# OpenTallas memory compiler (tools/mem_compiler), ASAP7 abstract view
VERSION 5.7 ;
BUSBITCHARS "[]" ;
DIVIDERCHAR "/" ;
PROPERTYDEFINITIONS
  MACRO width INTEGER ;
  MACRO depth INTEGER ;
  MACRO banks INTEGER ;
END PROPERTYDEFINITIONS
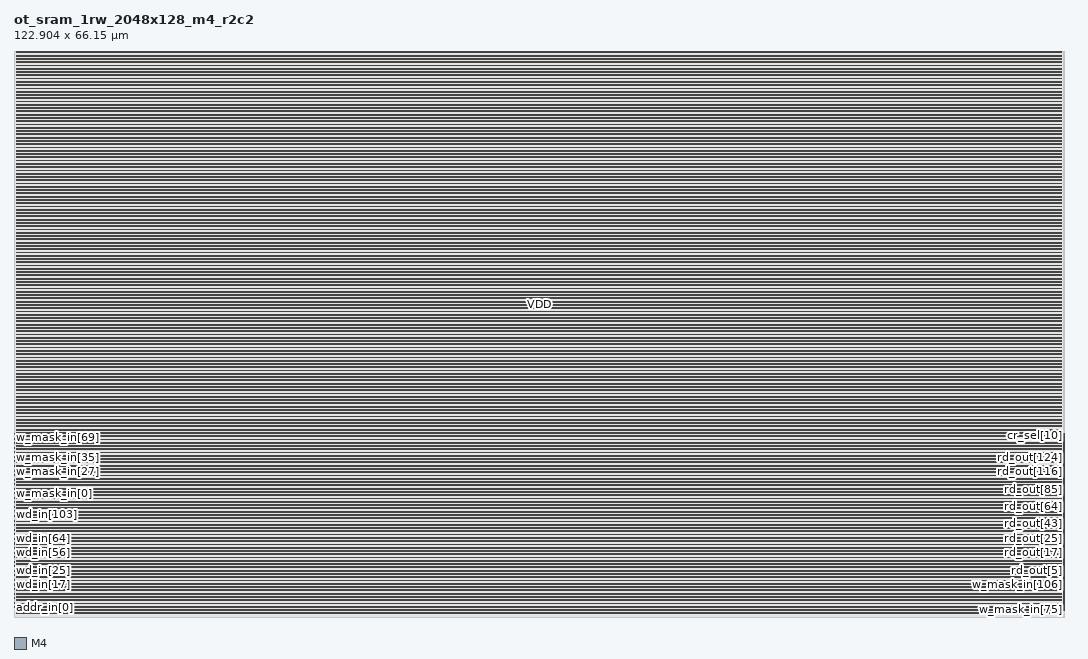
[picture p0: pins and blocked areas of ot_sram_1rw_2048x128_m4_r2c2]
MACRO ot_sram_1rw_2048x128_m4_r2c2
  PROPERTY width 128 ;
  PROPERTY depth 2048 ;
  PROPERTY banks 1 ;
  FOREIGN ot_sram_1rw_2048x128_m4_r2c2 0 0 ;
  SYMMETRY X Y R90 ;
  SIZE 122.904 BY 66.150 ;
  CLASS BLOCK ;
  PIN clk
    DIRECTION INPUT ;
    USE CLOCK ;
    SHAPE ABUTMENT ;
    PORT
      LAYER M4 ;
      RECT 0.000 0.768 0.024 0.792 ;
    END
  END clk
  PIN ce_in
    DIRECTION INPUT ;
    USE SIGNAL ;
    SHAPE ABUTMENT ;
    PORT
      LAYER M4 ;
      RECT 0.000 0.864 0.024 0.888 ;
    END
  END ce_in
  PIN we_in
    DIRECTION INPUT ;
    USE SIGNAL ;
    SHAPE ABUTMENT ;
    PORT
      LAYER M4 ;
      RECT 0.000 0.960 0.024 0.984 ;
    END
  END we_in
  PIN addr_in[0]
    DIRECTION INPUT ;
    USE SIGNAL ;
    SHAPE ABUTMENT ;
    PORT
      LAYER M4 ;
      RECT 0.000 1.056 0.024 1.080 ;
    END
  END addr_in[0]
  PIN addr_in[1]
    DIRECTION INPUT ;
    USE SIGNAL ;
    SHAPE ABUTMENT ;
    PORT
      LAYER M4 ;
      RECT 0.000 1.152 0.024 1.176 ;
    END
  END addr_in[1]
  PIN addr_in[2]
    DIRECTION INPUT ;
    USE SIGNAL ;
    SHAPE ABUTMENT ;
    PORT
      LAYER M4 ;
      RECT 0.000 1.248 0.024 1.272 ;
    END
  END addr_in[2]
  PIN addr_in[3]
    DIRECTION INPUT ;
    USE SIGNAL ;
    SHAPE ABUTMENT ;
    PORT
      LAYER M4 ;
      RECT 0.000 1.344 0.024 1.368 ;
    END
  END addr_in[3]
  PIN addr_in[4]
    DIRECTION INPUT ;
    USE SIGNAL ;
    SHAPE ABUTMENT ;
    PORT
      LAYER M4 ;
      RECT 0.000 1.440 0.024 1.464 ;
    END
  END addr_in[4]
  PIN addr_in[5]
    DIRECTION INPUT ;
    USE SIGNAL ;
    SHAPE ABUTMENT ;
    PORT
      LAYER M4 ;
      RECT 0.000 1.536 0.024 1.560 ;
    END
  END addr_in[5]
  PIN addr_in[6]
    DIRECTION INPUT ;
    USE SIGNAL ;
    SHAPE ABUTMENT ;
    PORT
      LAYER M4 ;
      RECT 0.000 1.632 0.024 1.656 ;
    END
  END addr_in[6]
  PIN addr_in[7]
    DIRECTION INPUT ;
    USE SIGNAL ;
    SHAPE ABUTMENT ;
    PORT
      LAYER M4 ;
      RECT 0.000 1.728 0.024 1.752 ;
    END
  END addr_in[7]
  PIN addr_in[8]
    DIRECTION INPUT ;
    USE SIGNAL ;
    SHAPE ABUTMENT ;
    PORT
      LAYER M4 ;
      RECT 0.000 1.824 0.024 1.848 ;
    END
  END addr_in[8]
  PIN addr_in[9]
    DIRECTION INPUT ;
    USE SIGNAL ;
    SHAPE ABUTMENT ;
    PORT
      LAYER M4 ;
      RECT 0.000 1.920 0.024 1.944 ;
    END
  END addr_in[9]
  PIN addr_in[10]
    DIRECTION INPUT ;
    USE SIGNAL ;
    SHAPE ABUTMENT ;
    PORT
      LAYER M4 ;
      RECT 0.000 2.016 0.024 2.040 ;
    END
  END addr_in[10]
  PIN wd_in[0]
    DIRECTION INPUT ;
    USE SIGNAL ;
    SHAPE ABUTMENT ;
    PORT
      LAYER M4 ;
      RECT 0.000 2.112 0.024 2.136 ;
    END
  END wd_in[0]
  PIN wd_in[1]
    DIRECTION INPUT ;
    USE SIGNAL ;
    SHAPE ABUTMENT ;
    PORT
      LAYER M4 ;
      RECT 0.000 2.208 0.024 2.232 ;
    END
  END wd_in[1]
  PIN wd_in[2]
    DIRECTION INPUT ;
    USE SIGNAL ;
    SHAPE ABUTMENT ;
    PORT
      LAYER M4 ;
      RECT 0.000 2.304 0.024 2.328 ;
    END
  END wd_in[2]
  PIN wd_in[3]
    DIRECTION INPUT ;
    USE SIGNAL ;
    SHAPE ABUTMENT ;
    PORT
      LAYER M4 ;
      RECT 0.000 2.400 0.024 2.424 ;
    END
  END wd_in[3]
  PIN wd_in[4]
    DIRECTION INPUT ;
    USE SIGNAL ;
    SHAPE ABUTMENT ;
    PORT
      LAYER M4 ;
      RECT 0.000 2.496 0.024 2.520 ;
    END
  END wd_in[4]
  PIN wd_in[5]
    DIRECTION INPUT ;
    USE SIGNAL ;
    SHAPE ABUTMENT ;
    PORT
      LAYER M4 ;
      RECT 0.000 2.592 0.024 2.616 ;
    END
  END wd_in[5]
  PIN wd_in[6]
    DIRECTION INPUT ;
    USE SIGNAL ;
    SHAPE ABUTMENT ;
    PORT
      LAYER M4 ;
      RECT 0.000 2.688 0.024 2.712 ;
    END
  END wd_in[6]
  PIN wd_in[7]
    DIRECTION INPUT ;
    USE SIGNAL ;
    SHAPE ABUTMENT ;
    PORT
      LAYER M4 ;
      RECT 0.000 2.784 0.024 2.808 ;
    END
  END wd_in[7]
  PIN wd_in[8]
    DIRECTION INPUT ;
    USE SIGNAL ;
    SHAPE ABUTMENT ;
    PORT
      LAYER M4 ;
      RECT 0.000 2.880 0.024 2.904 ;
    END
  END wd_in[8]
  PIN wd_in[9]
    DIRECTION INPUT ;
    USE SIGNAL ;
    SHAPE ABUTMENT ;
    PORT
      LAYER M4 ;
      RECT 0.000 2.976 0.024 3.000 ;
    END
  END wd_in[9]
  PIN wd_in[10]
    DIRECTION INPUT ;
    USE SIGNAL ;
    SHAPE ABUTMENT ;
    PORT
      LAYER M4 ;
      RECT 0.000 3.072 0.024 3.096 ;
    END
  END wd_in[10]
  PIN wd_in[11]
    DIRECTION INPUT ;
    USE SIGNAL ;
    SHAPE ABUTMENT ;
    PORT
      LAYER M4 ;
      RECT 0.000 3.168 0.024 3.192 ;
    END
  END wd_in[11]
  PIN wd_in[12]
    DIRECTION INPUT ;
    USE SIGNAL ;
    SHAPE ABUTMENT ;
    PORT
      LAYER M4 ;
      RECT 0.000 3.264 0.024 3.288 ;
    END
  END wd_in[12]
  PIN wd_in[13]
    DIRECTION INPUT ;
    USE SIGNAL ;
    SHAPE ABUTMENT ;
    PORT
      LAYER M4 ;
      RECT 0.000 3.360 0.024 3.384 ;
    END
  END wd_in[13]
  PIN wd_in[14]
    DIRECTION INPUT ;
    USE SIGNAL ;
    SHAPE ABUTMENT ;
    PORT
      LAYER M4 ;
      RECT 0.000 3.456 0.024 3.480 ;
    END
  END wd_in[14]
  PIN wd_in[15]
    DIRECTION INPUT ;
    USE SIGNAL ;
    SHAPE ABUTMENT ;
    PORT
      LAYER M4 ;
      RECT 0.000 3.552 0.024 3.576 ;
    END
  END wd_in[15]
  PIN wd_in[16]
    DIRECTION INPUT ;
    USE SIGNAL ;
    SHAPE ABUTMENT ;
    PORT
      LAYER M4 ;
      RECT 0.000 3.648 0.024 3.672 ;
    END
  END wd_in[16]
  PIN wd_in[17]
    DIRECTION INPUT ;
    USE SIGNAL ;
    SHAPE ABUTMENT ;
    PORT
      LAYER M4 ;
      RECT 0.000 3.744 0.024 3.768 ;
    END
  END wd_in[17]
  PIN wd_in[18]
    DIRECTION INPUT ;
    USE SIGNAL ;
    SHAPE ABUTMENT ;
    PORT
      LAYER M4 ;
      RECT 0.000 3.840 0.024 3.864 ;
    END
  END wd_in[18]
  PIN wd_in[19]
    DIRECTION INPUT ;
    USE SIGNAL ;
    SHAPE ABUTMENT ;
    PORT
      LAYER M4 ;
      RECT 0.000 3.936 0.024 3.960 ;
    END
  END wd_in[19]
  PIN wd_in[20]
    DIRECTION INPUT ;
    USE SIGNAL ;
    SHAPE ABUTMENT ;
    PORT
      LAYER M4 ;
      RECT 0.000 4.032 0.024 4.056 ;
    END
  END wd_in[20]
  PIN wd_in[21]
    DIRECTION INPUT ;
    USE SIGNAL ;
    SHAPE ABUTMENT ;
    PORT
      LAYER M4 ;
      RECT 0.000 4.128 0.024 4.152 ;
    END
  END wd_in[21]
  PIN wd_in[22]
    DIRECTION INPUT ;
    USE SIGNAL ;
    SHAPE ABUTMENT ;
    PORT
      LAYER M4 ;
      RECT 0.000 4.224 0.024 4.248 ;
    END
  END wd_in[22]
  PIN wd_in[23]
    DIRECTION INPUT ;
    USE SIGNAL ;
    SHAPE ABUTMENT ;
    PORT
      LAYER M4 ;
      RECT 0.000 4.320 0.024 4.344 ;
    END
  END wd_in[23]
  PIN wd_in[24]
    DIRECTION INPUT ;
    USE SIGNAL ;
    SHAPE ABUTMENT ;
    PORT
      LAYER M4 ;
      RECT 0.000 4.416 0.024 4.440 ;
    END
  END wd_in[24]
  PIN wd_in[25]
    DIRECTION INPUT ;
    USE SIGNAL ;
    SHAPE ABUTMENT ;
    PORT
      LAYER M4 ;
      RECT 0.000 4.512 0.024 4.536 ;
    END
  END wd_in[25]
  PIN wd_in[26]
    DIRECTION INPUT ;
    USE SIGNAL ;
    SHAPE ABUTMENT ;
    PORT
      LAYER M4 ;
      RECT 0.000 4.608 0.024 4.632 ;
    END
  END wd_in[26]
  PIN wd_in[27]
    DIRECTION INPUT ;
    USE SIGNAL ;
    SHAPE ABUTMENT ;
    PORT
      LAYER M4 ;
      RECT 0.000 4.704 0.024 4.728 ;
    END
  END wd_in[27]
  PIN wd_in[28]
    DIRECTION INPUT ;
    USE SIGNAL ;
    SHAPE ABUTMENT ;
    PORT
      LAYER M4 ;
      RECT 0.000 4.800 0.024 4.824 ;
    END
  END wd_in[28]
  PIN wd_in[29]
    DIRECTION INPUT ;
    USE SIGNAL ;
    SHAPE ABUTMENT ;
    PORT
      LAYER M4 ;
      RECT 0.000 4.896 0.024 4.920 ;
    END
  END wd_in[29]
  PIN wd_in[30]
    DIRECTION INPUT ;
    USE SIGNAL ;
    SHAPE ABUTMENT ;
    PORT
      LAYER M4 ;
      RECT 0.000 4.992 0.024 5.016 ;
    END
  END wd_in[30]
  PIN wd_in[31]
    DIRECTION INPUT ;
    USE SIGNAL ;
    SHAPE ABUTMENT ;
    PORT
      LAYER M4 ;
      RECT 0.000 5.088 0.024 5.112 ;
    END
  END wd_in[31]
  PIN wd_in[32]
    DIRECTION INPUT ;
    USE SIGNAL ;
    SHAPE ABUTMENT ;
    PORT
      LAYER M4 ;
      RECT 0.000 5.184 0.024 5.208 ;
    END
  END wd_in[32]
  PIN wd_in[33]
    DIRECTION INPUT ;
    USE SIGNAL ;
    SHAPE ABUTMENT ;
    PORT
      LAYER M4 ;
      RECT 0.000 5.280 0.024 5.304 ;
    END
  END wd_in[33]
  PIN wd_in[34]
    DIRECTION INPUT ;
    USE SIGNAL ;
    SHAPE ABUTMENT ;
    PORT
      LAYER M4 ;
      RECT 0.000 5.376 0.024 5.400 ;
    END
  END wd_in[34]
  PIN wd_in[35]
    DIRECTION INPUT ;
    USE SIGNAL ;
    SHAPE ABUTMENT ;
    PORT
      LAYER M4 ;
      RECT 0.000 5.472 0.024 5.496 ;
    END
  END wd_in[35]
  PIN wd_in[36]
    DIRECTION INPUT ;
    USE SIGNAL ;
    SHAPE ABUTMENT ;
    PORT
      LAYER M4 ;
      RECT 0.000 5.568 0.024 5.592 ;
    END
  END wd_in[36]
  PIN wd_in[37]
    DIRECTION INPUT ;
    USE SIGNAL ;
    SHAPE ABUTMENT ;
    PORT
      LAYER M4 ;
      RECT 0.000 5.664 0.024 5.688 ;
    END
  END wd_in[37]
  PIN wd_in[38]
    DIRECTION INPUT ;
    USE SIGNAL ;
    SHAPE ABUTMENT ;
    PORT
      LAYER M4 ;
      RECT 0.000 5.760 0.024 5.784 ;
    END
  END wd_in[38]
  PIN wd_in[39]
    DIRECTION INPUT ;
    USE SIGNAL ;
    SHAPE ABUTMENT ;
    PORT
      LAYER M4 ;
      RECT 0.000 5.856 0.024 5.880 ;
    END
  END wd_in[39]
  PIN wd_in[40]
    DIRECTION INPUT ;
    USE SIGNAL ;
    SHAPE ABUTMENT ;
    PORT
      LAYER M4 ;
      RECT 0.000 5.952 0.024 5.976 ;
    END
  END wd_in[40]
  PIN wd_in[41]
    DIRECTION INPUT ;
    USE SIGNAL ;
    SHAPE ABUTMENT ;
    PORT
      LAYER M4 ;
      RECT 0.000 6.048 0.024 6.072 ;
    END
  END wd_in[41]
  PIN wd_in[42]
    DIRECTION INPUT ;
    USE SIGNAL ;
    SHAPE ABUTMENT ;
    PORT
      LAYER M4 ;
      RECT 0.000 6.144 0.024 6.168 ;
    END
  END wd_in[42]
  PIN wd_in[43]
    DIRECTION INPUT ;
    USE SIGNAL ;
    SHAPE ABUTMENT ;
    PORT
      LAYER M4 ;
      RECT 0.000 6.240 0.024 6.264 ;
    END
  END wd_in[43]
  PIN wd_in[44]
    DIRECTION INPUT ;
    USE SIGNAL ;
    SHAPE ABUTMENT ;
    PORT
      LAYER M4 ;
      RECT 0.000 6.336 0.024 6.360 ;
    END
  END wd_in[44]
  PIN wd_in[45]
    DIRECTION INPUT ;
    USE SIGNAL ;
    SHAPE ABUTMENT ;
    PORT
      LAYER M4 ;
      RECT 0.000 6.432 0.024 6.456 ;
    END
  END wd_in[45]
  PIN wd_in[46]
    DIRECTION INPUT ;
    USE SIGNAL ;
    SHAPE ABUTMENT ;
    PORT
      LAYER M4 ;
      RECT 0.000 6.528 0.024 6.552 ;
    END
  END wd_in[46]
  PIN wd_in[47]
    DIRECTION INPUT ;
    USE SIGNAL ;
    SHAPE ABUTMENT ;
    PORT
      LAYER M4 ;
      RECT 0.000 6.624 0.024 6.648 ;
    END
  END wd_in[47]
  PIN wd_in[48]
    DIRECTION INPUT ;
    USE SIGNAL ;
    SHAPE ABUTMENT ;
    PORT
      LAYER M4 ;
      RECT 0.000 6.720 0.024 6.744 ;
    END
  END wd_in[48]
  PIN wd_in[49]
    DIRECTION INPUT ;
    USE SIGNAL ;
    SHAPE ABUTMENT ;
    PORT
      LAYER M4 ;
      RECT 0.000 6.816 0.024 6.840 ;
    END
  END wd_in[49]
  PIN wd_in[50]
    DIRECTION INPUT ;
    USE SIGNAL ;
    SHAPE ABUTMENT ;
    PORT
      LAYER M4 ;
      RECT 0.000 6.912 0.024 6.936 ;
    END
  END wd_in[50]
  PIN wd_in[51]
    DIRECTION INPUT ;
    USE SIGNAL ;
    SHAPE ABUTMENT ;
    PORT
      LAYER M4 ;
      RECT 0.000 7.008 0.024 7.032 ;
    END
  END wd_in[51]
  PIN wd_in[52]
    DIRECTION INPUT ;
    USE SIGNAL ;
    SHAPE ABUTMENT ;
    PORT
      LAYER M4 ;
      RECT 0.000 7.104 0.024 7.128 ;
    END
  END wd_in[52]
  PIN wd_in[53]
    DIRECTION INPUT ;
    USE SIGNAL ;
    SHAPE ABUTMENT ;
    PORT
      LAYER M4 ;
      RECT 0.000 7.200 0.024 7.224 ;
    END
  END wd_in[53]
  PIN wd_in[54]
    DIRECTION INPUT ;
    USE SIGNAL ;
    SHAPE ABUTMENT ;
    PORT
      LAYER M4 ;
      RECT 0.000 7.296 0.024 7.320 ;
    END
  END wd_in[54]
  PIN wd_in[55]
    DIRECTION INPUT ;
    USE SIGNAL ;
    SHAPE ABUTMENT ;
    PORT
      LAYER M4 ;
      RECT 0.000 7.392 0.024 7.416 ;
    END
  END wd_in[55]
  PIN wd_in[56]
    DIRECTION INPUT ;
    USE SIGNAL ;
    SHAPE ABUTMENT ;
    PORT
      LAYER M4 ;
      RECT 0.000 7.488 0.024 7.512 ;
    END
  END wd_in[56]
  PIN wd_in[57]
    DIRECTION INPUT ;
    USE SIGNAL ;
    SHAPE ABUTMENT ;
    PORT
      LAYER M4 ;
      RECT 0.000 7.584 0.024 7.608 ;
    END
  END wd_in[57]
  PIN wd_in[58]
    DIRECTION INPUT ;
    USE SIGNAL ;
    SHAPE ABUTMENT ;
    PORT
      LAYER M4 ;
      RECT 0.000 7.680 0.024 7.704 ;
    END
  END wd_in[58]
  PIN wd_in[59]
    DIRECTION INPUT ;
    USE SIGNAL ;
    SHAPE ABUTMENT ;
    PORT
      LAYER M4 ;
      RECT 0.000 7.776 0.024 7.800 ;
    END
  END wd_in[59]
  PIN wd_in[60]
    DIRECTION INPUT ;
    USE SIGNAL ;
    SHAPE ABUTMENT ;
    PORT
      LAYER M4 ;
      RECT 0.000 7.872 0.024 7.896 ;
    END
  END wd_in[60]
  PIN wd_in[61]
    DIRECTION INPUT ;
    USE SIGNAL ;
    SHAPE ABUTMENT ;
    PORT
      LAYER M4 ;
      RECT 0.000 7.968 0.024 7.992 ;
    END
  END wd_in[61]
  PIN wd_in[62]
    DIRECTION INPUT ;
    USE SIGNAL ;
    SHAPE ABUTMENT ;
    PORT
      LAYER M4 ;
      RECT 0.000 8.064 0.024 8.088 ;
    END
  END wd_in[62]
  PIN wd_in[63]
    DIRECTION INPUT ;
    USE SIGNAL ;
    SHAPE ABUTMENT ;
    PORT
      LAYER M4 ;
      RECT 0.000 8.160 0.024 8.184 ;
    END
  END wd_in[63]
  PIN wd_in[64]
    DIRECTION INPUT ;
    USE SIGNAL ;
    SHAPE ABUTMENT ;
    PORT
      LAYER M4 ;
      RECT 0.000 8.256 0.024 8.280 ;
    END
  END wd_in[64]
  PIN wd_in[65]
    DIRECTION INPUT ;
    USE SIGNAL ;
    SHAPE ABUTMENT ;
    PORT
      LAYER M4 ;
      RECT 0.000 8.352 0.024 8.376 ;
    END
  END wd_in[65]
  PIN wd_in[66]
    DIRECTION INPUT ;
    USE SIGNAL ;
    SHAPE ABUTMENT ;
    PORT
      LAYER M4 ;
      RECT 0.000 8.448 0.024 8.472 ;
    END
  END wd_in[66]
  PIN wd_in[67]
    DIRECTION INPUT ;
    USE SIGNAL ;
    SHAPE ABUTMENT ;
    PORT
      LAYER M4 ;
      RECT 0.000 8.544 0.024 8.568 ;
    END
  END wd_in[67]
  PIN wd_in[68]
    DIRECTION INPUT ;
    USE SIGNAL ;
    SHAPE ABUTMENT ;
    PORT
      LAYER M4 ;
      RECT 0.000 8.640 0.024 8.664 ;
    END
  END wd_in[68]
  PIN wd_in[69]
    DIRECTION INPUT ;
    USE SIGNAL ;
    SHAPE ABUTMENT ;
    PORT
      LAYER M4 ;
      RECT 0.000 8.736 0.024 8.760 ;
    END
  END wd_in[69]
  PIN wd_in[70]
    DIRECTION INPUT ;
    USE SIGNAL ;
    SHAPE ABUTMENT ;
    PORT
      LAYER M4 ;
      RECT 0.000 8.832 0.024 8.856 ;
    END
  END wd_in[70]
  PIN wd_in[71]
    DIRECTION INPUT ;
    USE SIGNAL ;
    SHAPE ABUTMENT ;
    PORT
      LAYER M4 ;
      RECT 0.000 8.928 0.024 8.952 ;
    END
  END wd_in[71]
  PIN wd_in[72]
    DIRECTION INPUT ;
    USE SIGNAL ;
    SHAPE ABUTMENT ;
    PORT
      LAYER M4 ;
      RECT 0.000 9.024 0.024 9.048 ;
    END
  END wd_in[72]
  PIN wd_in[73]
    DIRECTION INPUT ;
    USE SIGNAL ;
    SHAPE ABUTMENT ;
    PORT
      LAYER M4 ;
      RECT 0.000 9.120 0.024 9.144 ;
    END
  END wd_in[73]
  PIN wd_in[74]
    DIRECTION INPUT ;
    USE SIGNAL ;
    SHAPE ABUTMENT ;
    PORT
      LAYER M4 ;
      RECT 0.000 9.216 0.024 9.240 ;
    END
  END wd_in[74]
  PIN wd_in[75]
    DIRECTION INPUT ;
    USE SIGNAL ;
    SHAPE ABUTMENT ;
    PORT
      LAYER M4 ;
      RECT 0.000 9.312 0.024 9.336 ;
    END
  END wd_in[75]
  PIN wd_in[76]
    DIRECTION INPUT ;
    USE SIGNAL ;
    SHAPE ABUTMENT ;
    PORT
      LAYER M4 ;
      RECT 0.000 9.408 0.024 9.432 ;
    END
  END wd_in[76]
  PIN wd_in[77]
    DIRECTION INPUT ;
    USE SIGNAL ;
    SHAPE ABUTMENT ;
    PORT
      LAYER M4 ;
      RECT 0.000 9.504 0.024 9.528 ;
    END
  END wd_in[77]
  PIN wd_in[78]
    DIRECTION INPUT ;
    USE SIGNAL ;
    SHAPE ABUTMENT ;
    PORT
      LAYER M4 ;
      RECT 0.000 9.600 0.024 9.624 ;
    END
  END wd_in[78]
  PIN wd_in[79]
    DIRECTION INPUT ;
    USE SIGNAL ;
    SHAPE ABUTMENT ;
    PORT
      LAYER M4 ;
      RECT 0.000 9.696 0.024 9.720 ;
    END
  END wd_in[79]
  PIN wd_in[80]
    DIRECTION INPUT ;
    USE SIGNAL ;
    SHAPE ABUTMENT ;
    PORT
      LAYER M4 ;
      RECT 0.000 9.792 0.024 9.816 ;
    END
  END wd_in[80]
  PIN wd_in[81]
    DIRECTION INPUT ;
    USE SIGNAL ;
    SHAPE ABUTMENT ;
    PORT
      LAYER M4 ;
      RECT 0.000 9.888 0.024 9.912 ;
    END
  END wd_in[81]
  PIN wd_in[82]
    DIRECTION INPUT ;
    USE SIGNAL ;
    SHAPE ABUTMENT ;
    PORT
      LAYER M4 ;
      RECT 0.000 9.984 0.024 10.008 ;
    END
  END wd_in[82]
  PIN wd_in[83]
    DIRECTION INPUT ;
    USE SIGNAL ;
    SHAPE ABUTMENT ;
    PORT
      LAYER M4 ;
      RECT 0.000 10.080 0.024 10.104 ;
    END
  END wd_in[83]
  PIN wd_in[84]
    DIRECTION INPUT ;
    USE SIGNAL ;
    SHAPE ABUTMENT ;
    PORT
      LAYER M4 ;
      RECT 0.000 10.176 0.024 10.200 ;
    END
  END wd_in[84]
  PIN wd_in[85]
    DIRECTION INPUT ;
    USE SIGNAL ;
    SHAPE ABUTMENT ;
    PORT
      LAYER M4 ;
      RECT 0.000 10.272 0.024 10.296 ;
    END
  END wd_in[85]
  PIN wd_in[86]
    DIRECTION INPUT ;
    USE SIGNAL ;
    SHAPE ABUTMENT ;
    PORT
      LAYER M4 ;
      RECT 0.000 10.368 0.024 10.392 ;
    END
  END wd_in[86]
  PIN wd_in[87]
    DIRECTION INPUT ;
    USE SIGNAL ;
    SHAPE ABUTMENT ;
    PORT
      LAYER M4 ;
      RECT 0.000 10.464 0.024 10.488 ;
    END
  END wd_in[87]
  PIN wd_in[88]
    DIRECTION INPUT ;
    USE SIGNAL ;
    SHAPE ABUTMENT ;
    PORT
      LAYER M4 ;
      RECT 0.000 10.560 0.024 10.584 ;
    END
  END wd_in[88]
  PIN wd_in[89]
    DIRECTION INPUT ;
    USE SIGNAL ;
    SHAPE ABUTMENT ;
    PORT
      LAYER M4 ;
      RECT 0.000 10.656 0.024 10.680 ;
    END
  END wd_in[89]
  PIN wd_in[90]
    DIRECTION INPUT ;
    USE SIGNAL ;
    SHAPE ABUTMENT ;
    PORT
      LAYER M4 ;
      RECT 0.000 10.752 0.024 10.776 ;
    END
  END wd_in[90]
  PIN wd_in[91]
    DIRECTION INPUT ;
    USE SIGNAL ;
    SHAPE ABUTMENT ;
    PORT
      LAYER M4 ;
      RECT 0.000 10.848 0.024 10.872 ;
    END
  END wd_in[91]
  PIN wd_in[92]
    DIRECTION INPUT ;
    USE SIGNAL ;
    SHAPE ABUTMENT ;
    PORT
      LAYER M4 ;
      RECT 0.000 10.944 0.024 10.968 ;
    END
  END wd_in[92]
  PIN wd_in[93]
    DIRECTION INPUT ;
    USE SIGNAL ;
    SHAPE ABUTMENT ;
    PORT
      LAYER M4 ;
      RECT 0.000 11.040 0.024 11.064 ;
    END
  END wd_in[93]
  PIN wd_in[94]
    DIRECTION INPUT ;
    USE SIGNAL ;
    SHAPE ABUTMENT ;
    PORT
      LAYER M4 ;
      RECT 0.000 11.136 0.024 11.160 ;
    END
  END wd_in[94]
  PIN wd_in[95]
    DIRECTION INPUT ;
    USE SIGNAL ;
    SHAPE ABUTMENT ;
    PORT
      LAYER M4 ;
      RECT 0.000 11.232 0.024 11.256 ;
    END
  END wd_in[95]
  PIN wd_in[96]
    DIRECTION INPUT ;
    USE SIGNAL ;
    SHAPE ABUTMENT ;
    PORT
      LAYER M4 ;
      RECT 0.000 11.328 0.024 11.352 ;
    END
  END wd_in[96]
  PIN wd_in[97]
    DIRECTION INPUT ;
    USE SIGNAL ;
    SHAPE ABUTMENT ;
    PORT
      LAYER M4 ;
      RECT 0.000 11.424 0.024 11.448 ;
    END
  END wd_in[97]
  PIN wd_in[98]
    DIRECTION INPUT ;
    USE SIGNAL ;
    SHAPE ABUTMENT ;
    PORT
      LAYER M4 ;
      RECT 0.000 11.520 0.024 11.544 ;
    END
  END wd_in[98]
  PIN wd_in[99]
    DIRECTION INPUT ;
    USE SIGNAL ;
    SHAPE ABUTMENT ;
    PORT
      LAYER M4 ;
      RECT 0.000 11.616 0.024 11.640 ;
    END
  END wd_in[99]
  PIN wd_in[100]
    DIRECTION INPUT ;
    USE SIGNAL ;
    SHAPE ABUTMENT ;
    PORT
      LAYER M4 ;
      RECT 0.000 11.712 0.024 11.736 ;
    END
  END wd_in[100]
  PIN wd_in[101]
    DIRECTION INPUT ;
    USE SIGNAL ;
    SHAPE ABUTMENT ;
    PORT
      LAYER M4 ;
      RECT 0.000 11.808 0.024 11.832 ;
    END
  END wd_in[101]
  PIN wd_in[102]
    DIRECTION INPUT ;
    USE SIGNAL ;
    SHAPE ABUTMENT ;
    PORT
      LAYER M4 ;
      RECT 0.000 11.904 0.024 11.928 ;
    END
  END wd_in[102]
  PIN wd_in[103]
    DIRECTION INPUT ;
    USE SIGNAL ;
    SHAPE ABUTMENT ;
    PORT
      LAYER M4 ;
      RECT 0.000 12.000 0.024 12.024 ;
    END
  END wd_in[103]
  PIN wd_in[104]
    DIRECTION INPUT ;
    USE SIGNAL ;
    SHAPE ABUTMENT ;
    PORT
      LAYER M4 ;
      RECT 0.000 12.096 0.024 12.120 ;
    END
  END wd_in[104]
  PIN wd_in[105]
    DIRECTION INPUT ;
    USE SIGNAL ;
    SHAPE ABUTMENT ;
    PORT
      LAYER M4 ;
      RECT 0.000 12.192 0.024 12.216 ;
    END
  END wd_in[105]
  PIN wd_in[106]
    DIRECTION INPUT ;
    USE SIGNAL ;
    SHAPE ABUTMENT ;
    PORT
      LAYER M4 ;
      RECT 0.000 12.288 0.024 12.312 ;
    END
  END wd_in[106]
  PIN wd_in[107]
    DIRECTION INPUT ;
    USE SIGNAL ;
    SHAPE ABUTMENT ;
    PORT
      LAYER M4 ;
      RECT 0.000 12.384 0.024 12.408 ;
    END
  END wd_in[107]
  PIN wd_in[108]
    DIRECTION INPUT ;
    USE SIGNAL ;
    SHAPE ABUTMENT ;
    PORT
      LAYER M4 ;
      RECT 0.000 12.480 0.024 12.504 ;
    END
  END wd_in[108]
  PIN wd_in[109]
    DIRECTION INPUT ;
    USE SIGNAL ;
    SHAPE ABUTMENT ;
    PORT
      LAYER M4 ;
      RECT 0.000 12.576 0.024 12.600 ;
    END
  END wd_in[109]
  PIN wd_in[110]
    DIRECTION INPUT ;
    USE SIGNAL ;
    SHAPE ABUTMENT ;
    PORT
      LAYER M4 ;
      RECT 0.000 12.672 0.024 12.696 ;
    END
  END wd_in[110]
  PIN wd_in[111]
    DIRECTION INPUT ;
    USE SIGNAL ;
    SHAPE ABUTMENT ;
    PORT
      LAYER M4 ;
      RECT 0.000 12.768 0.024 12.792 ;
    END
  END wd_in[111]
  PIN wd_in[112]
    DIRECTION INPUT ;
    USE SIGNAL ;
    SHAPE ABUTMENT ;
    PORT
      LAYER M4 ;
      RECT 0.000 12.864 0.024 12.888 ;
    END
  END wd_in[112]
  PIN wd_in[113]
    DIRECTION INPUT ;
    USE SIGNAL ;
    SHAPE ABUTMENT ;
    PORT
      LAYER M4 ;
      RECT 0.000 12.960 0.024 12.984 ;
    END
  END wd_in[113]
  PIN wd_in[114]
    DIRECTION INPUT ;
    USE SIGNAL ;
    SHAPE ABUTMENT ;
    PORT
      LAYER M4 ;
      RECT 0.000 13.056 0.024 13.080 ;
    END
  END wd_in[114]
  PIN wd_in[115]
    DIRECTION INPUT ;
    USE SIGNAL ;
    SHAPE ABUTMENT ;
    PORT
      LAYER M4 ;
      RECT 0.000 13.152 0.024 13.176 ;
    END
  END wd_in[115]
  PIN wd_in[116]
    DIRECTION INPUT ;
    USE SIGNAL ;
    SHAPE ABUTMENT ;
    PORT
      LAYER M4 ;
      RECT 0.000 13.248 0.024 13.272 ;
    END
  END wd_in[116]
  PIN wd_in[117]
    DIRECTION INPUT ;
    USE SIGNAL ;
    SHAPE ABUTMENT ;
    PORT
      LAYER M4 ;
      RECT 0.000 13.344 0.024 13.368 ;
    END
  END wd_in[117]
  PIN wd_in[118]
    DIRECTION INPUT ;
    USE SIGNAL ;
    SHAPE ABUTMENT ;
    PORT
      LAYER M4 ;
      RECT 0.000 13.440 0.024 13.464 ;
    END
  END wd_in[118]
  PIN wd_in[119]
    DIRECTION INPUT ;
    USE SIGNAL ;
    SHAPE ABUTMENT ;
    PORT
      LAYER M4 ;
      RECT 0.000 13.536 0.024 13.560 ;
    END
  END wd_in[119]
  PIN wd_in[120]
    DIRECTION INPUT ;
    USE SIGNAL ;
    SHAPE ABUTMENT ;
    PORT
      LAYER M4 ;
      RECT 0.000 13.632 0.024 13.656 ;
    END
  END wd_in[120]
  PIN wd_in[121]
    DIRECTION INPUT ;
    USE SIGNAL ;
    SHAPE ABUTMENT ;
    PORT
      LAYER M4 ;
      RECT 0.000 13.728 0.024 13.752 ;
    END
  END wd_in[121]
  PIN wd_in[122]
    DIRECTION INPUT ;
    USE SIGNAL ;
    SHAPE ABUTMENT ;
    PORT
      LAYER M4 ;
      RECT 0.000 13.824 0.024 13.848 ;
    END
  END wd_in[122]
  PIN wd_in[123]
    DIRECTION INPUT ;
    USE SIGNAL ;
    SHAPE ABUTMENT ;
    PORT
      LAYER M4 ;
      RECT 0.000 13.920 0.024 13.944 ;
    END
  END wd_in[123]
  PIN wd_in[124]
    DIRECTION INPUT ;
    USE SIGNAL ;
    SHAPE ABUTMENT ;
    PORT
      LAYER M4 ;
      RECT 0.000 14.016 0.024 14.040 ;
    END
  END wd_in[124]
  PIN wd_in[125]
    DIRECTION INPUT ;
    USE SIGNAL ;
    SHAPE ABUTMENT ;
    PORT
      LAYER M4 ;
      RECT 0.000 14.112 0.024 14.136 ;
    END
  END wd_in[125]
  PIN wd_in[126]
    DIRECTION INPUT ;
    USE SIGNAL ;
    SHAPE ABUTMENT ;
    PORT
      LAYER M4 ;
      RECT 0.000 14.208 0.024 14.232 ;
    END
  END wd_in[126]
  PIN wd_in[127]
    DIRECTION INPUT ;
    USE SIGNAL ;
    SHAPE ABUTMENT ;
    PORT
      LAYER M4 ;
      RECT 0.000 14.304 0.024 14.328 ;
    END
  END wd_in[127]
  PIN w_mask_in[0]
    DIRECTION INPUT ;
    USE SIGNAL ;
    SHAPE ABUTMENT ;
    PORT
      LAYER M4 ;
      RECT 0.000 14.400 0.024 14.424 ;
    END
  END w_mask_in[0]
  PIN w_mask_in[1]
    DIRECTION INPUT ;
    USE SIGNAL ;
    SHAPE ABUTMENT ;
    PORT
      LAYER M4 ;
      RECT 0.000 14.496 0.024 14.520 ;
    END
  END w_mask_in[1]
  PIN w_mask_in[2]
    DIRECTION INPUT ;
    USE SIGNAL ;
    SHAPE ABUTMENT ;
    PORT
      LAYER M4 ;
      RECT 0.000 14.592 0.024 14.616 ;
    END
  END w_mask_in[2]
  PIN w_mask_in[3]
    DIRECTION INPUT ;
    USE SIGNAL ;
    SHAPE ABUTMENT ;
    PORT
      LAYER M4 ;
      RECT 0.000 14.688 0.024 14.712 ;
    END
  END w_mask_in[3]
  PIN w_mask_in[4]
    DIRECTION INPUT ;
    USE SIGNAL ;
    SHAPE ABUTMENT ;
    PORT
      LAYER M4 ;
      RECT 0.000 14.784 0.024 14.808 ;
    END
  END w_mask_in[4]
  PIN w_mask_in[5]
    DIRECTION INPUT ;
    USE SIGNAL ;
    SHAPE ABUTMENT ;
    PORT
      LAYER M4 ;
      RECT 0.000 14.880 0.024 14.904 ;
    END
  END w_mask_in[5]
  PIN w_mask_in[6]
    DIRECTION INPUT ;
    USE SIGNAL ;
    SHAPE ABUTMENT ;
    PORT
      LAYER M4 ;
      RECT 0.000 14.976 0.024 15.000 ;
    END
  END w_mask_in[6]
  PIN w_mask_in[7]
    DIRECTION INPUT ;
    USE SIGNAL ;
    SHAPE ABUTMENT ;
    PORT
      LAYER M4 ;
      RECT 0.000 15.072 0.024 15.096 ;
    END
  END w_mask_in[7]
  PIN w_mask_in[8]
    DIRECTION INPUT ;
    USE SIGNAL ;
    SHAPE ABUTMENT ;
    PORT
      LAYER M4 ;
      RECT 0.000 15.168 0.024 15.192 ;
    END
  END w_mask_in[8]
  PIN w_mask_in[9]
    DIRECTION INPUT ;
    USE SIGNAL ;
    SHAPE ABUTMENT ;
    PORT
      LAYER M4 ;
      RECT 0.000 15.264 0.024 15.288 ;
    END
  END w_mask_in[9]
  PIN w_mask_in[10]
    DIRECTION INPUT ;
    USE SIGNAL ;
    SHAPE ABUTMENT ;
    PORT
      LAYER M4 ;
      RECT 0.000 15.360 0.024 15.384 ;
    END
  END w_mask_in[10]
  PIN w_mask_in[11]
    DIRECTION INPUT ;
    USE SIGNAL ;
    SHAPE ABUTMENT ;
    PORT
      LAYER M4 ;
      RECT 0.000 15.456 0.024 15.480 ;
    END
  END w_mask_in[11]
  PIN w_mask_in[12]
    DIRECTION INPUT ;
    USE SIGNAL ;
    SHAPE ABUTMENT ;
    PORT
      LAYER M4 ;
      RECT 0.000 15.552 0.024 15.576 ;
    END
  END w_mask_in[12]
  PIN w_mask_in[13]
    DIRECTION INPUT ;
    USE SIGNAL ;
    SHAPE ABUTMENT ;
    PORT
      LAYER M4 ;
      RECT 0.000 15.648 0.024 15.672 ;
    END
  END w_mask_in[13]
  PIN w_mask_in[14]
    DIRECTION INPUT ;
    USE SIGNAL ;
    SHAPE ABUTMENT ;
    PORT
      LAYER M4 ;
      RECT 0.000 15.744 0.024 15.768 ;
    END
  END w_mask_in[14]
  PIN w_mask_in[15]
    DIRECTION INPUT ;
    USE SIGNAL ;
    SHAPE ABUTMENT ;
    PORT
      LAYER M4 ;
      RECT 0.000 15.840 0.024 15.864 ;
    END
  END w_mask_in[15]
  PIN w_mask_in[16]
    DIRECTION INPUT ;
    USE SIGNAL ;
    SHAPE ABUTMENT ;
    PORT
      LAYER M4 ;
      RECT 0.000 15.936 0.024 15.960 ;
    END
  END w_mask_in[16]
  PIN w_mask_in[17]
    DIRECTION INPUT ;
    USE SIGNAL ;
    SHAPE ABUTMENT ;
    PORT
      LAYER M4 ;
      RECT 0.000 16.032 0.024 16.056 ;
    END
  END w_mask_in[17]
  PIN w_mask_in[18]
    DIRECTION INPUT ;
    USE SIGNAL ;
    SHAPE ABUTMENT ;
    PORT
      LAYER M4 ;
      RECT 0.000 16.128 0.024 16.152 ;
    END
  END w_mask_in[18]
  PIN w_mask_in[19]
    DIRECTION INPUT ;
    USE SIGNAL ;
    SHAPE ABUTMENT ;
    PORT
      LAYER M4 ;
      RECT 0.000 16.224 0.024 16.248 ;
    END
  END w_mask_in[19]
  PIN w_mask_in[20]
    DIRECTION INPUT ;
    USE SIGNAL ;
    SHAPE ABUTMENT ;
    PORT
      LAYER M4 ;
      RECT 0.000 16.320 0.024 16.344 ;
    END
  END w_mask_in[20]
  PIN w_mask_in[21]
    DIRECTION INPUT ;
    USE SIGNAL ;
    SHAPE ABUTMENT ;
    PORT
      LAYER M4 ;
      RECT 0.000 16.416 0.024 16.440 ;
    END
  END w_mask_in[21]
  PIN w_mask_in[22]
    DIRECTION INPUT ;
    USE SIGNAL ;
    SHAPE ABUTMENT ;
    PORT
      LAYER M4 ;
      RECT 0.000 16.512 0.024 16.536 ;
    END
  END w_mask_in[22]
  PIN w_mask_in[23]
    DIRECTION INPUT ;
    USE SIGNAL ;
    SHAPE ABUTMENT ;
    PORT
      LAYER M4 ;
      RECT 0.000 16.608 0.024 16.632 ;
    END
  END w_mask_in[23]
  PIN w_mask_in[24]
    DIRECTION INPUT ;
    USE SIGNAL ;
    SHAPE ABUTMENT ;
    PORT
      LAYER M4 ;
      RECT 0.000 16.704 0.024 16.728 ;
    END
  END w_mask_in[24]
  PIN w_mask_in[25]
    DIRECTION INPUT ;
    USE SIGNAL ;
    SHAPE ABUTMENT ;
    PORT
      LAYER M4 ;
      RECT 0.000 16.800 0.024 16.824 ;
    END
  END w_mask_in[25]
  PIN w_mask_in[26]
    DIRECTION INPUT ;
    USE SIGNAL ;
    SHAPE ABUTMENT ;
    PORT
      LAYER M4 ;
      RECT 0.000 16.896 0.024 16.920 ;
    END
  END w_mask_in[26]
  PIN w_mask_in[27]
    DIRECTION INPUT ;
    USE SIGNAL ;
    SHAPE ABUTMENT ;
    PORT
      LAYER M4 ;
      RECT 0.000 16.992 0.024 17.016 ;
    END
  END w_mask_in[27]
  PIN w_mask_in[28]
    DIRECTION INPUT ;
    USE SIGNAL ;
    SHAPE ABUTMENT ;
    PORT
      LAYER M4 ;
      RECT 0.000 17.088 0.024 17.112 ;
    END
  END w_mask_in[28]
  PIN w_mask_in[29]
    DIRECTION INPUT ;
    USE SIGNAL ;
    SHAPE ABUTMENT ;
    PORT
      LAYER M4 ;
      RECT 0.000 17.184 0.024 17.208 ;
    END
  END w_mask_in[29]
  PIN w_mask_in[30]
    DIRECTION INPUT ;
    USE SIGNAL ;
    SHAPE ABUTMENT ;
    PORT
      LAYER M4 ;
      RECT 0.000 17.280 0.024 17.304 ;
    END
  END w_mask_in[30]
  PIN w_mask_in[31]
    DIRECTION INPUT ;
    USE SIGNAL ;
    SHAPE ABUTMENT ;
    PORT
      LAYER M4 ;
      RECT 0.000 17.376 0.024 17.400 ;
    END
  END w_mask_in[31]
  PIN w_mask_in[32]
    DIRECTION INPUT ;
    USE SIGNAL ;
    SHAPE ABUTMENT ;
    PORT
      LAYER M4 ;
      RECT 0.000 17.472 0.024 17.496 ;
    END
  END w_mask_in[32]
  PIN w_mask_in[33]
    DIRECTION INPUT ;
    USE SIGNAL ;
    SHAPE ABUTMENT ;
    PORT
      LAYER M4 ;
      RECT 0.000 17.568 0.024 17.592 ;
    END
  END w_mask_in[33]
  PIN w_mask_in[34]
    DIRECTION INPUT ;
    USE SIGNAL ;
    SHAPE ABUTMENT ;
    PORT
      LAYER M4 ;
      RECT 0.000 17.664 0.024 17.688 ;
    END
  END w_mask_in[34]
  PIN w_mask_in[35]
    DIRECTION INPUT ;
    USE SIGNAL ;
    SHAPE ABUTMENT ;
    PORT
      LAYER M4 ;
      RECT 0.000 17.760 0.024 17.784 ;
    END
  END w_mask_in[35]
  PIN w_mask_in[36]
    DIRECTION INPUT ;
    USE SIGNAL ;
    SHAPE ABUTMENT ;
    PORT
      LAYER M4 ;
      RECT 0.000 17.856 0.024 17.880 ;
    END
  END w_mask_in[36]
  PIN w_mask_in[37]
    DIRECTION INPUT ;
    USE SIGNAL ;
    SHAPE ABUTMENT ;
    PORT
      LAYER M4 ;
      RECT 0.000 17.952 0.024 17.976 ;
    END
  END w_mask_in[37]
  PIN w_mask_in[38]
    DIRECTION INPUT ;
    USE SIGNAL ;
    SHAPE ABUTMENT ;
    PORT
      LAYER M4 ;
      RECT 0.000 18.048 0.024 18.072 ;
    END
  END w_mask_in[38]
  PIN w_mask_in[39]
    DIRECTION INPUT ;
    USE SIGNAL ;
    SHAPE ABUTMENT ;
    PORT
      LAYER M4 ;
      RECT 0.000 18.144 0.024 18.168 ;
    END
  END w_mask_in[39]
  PIN w_mask_in[40]
    DIRECTION INPUT ;
    USE SIGNAL ;
    SHAPE ABUTMENT ;
    PORT
      LAYER M4 ;
      RECT 0.000 18.240 0.024 18.264 ;
    END
  END w_mask_in[40]
  PIN w_mask_in[41]
    DIRECTION INPUT ;
    USE SIGNAL ;
    SHAPE ABUTMENT ;
    PORT
      LAYER M4 ;
      RECT 0.000 18.336 0.024 18.360 ;
    END
  END w_mask_in[41]
  PIN w_mask_in[42]
    DIRECTION INPUT ;
    USE SIGNAL ;
    SHAPE ABUTMENT ;
    PORT
      LAYER M4 ;
      RECT 0.000 18.432 0.024 18.456 ;
    END
  END w_mask_in[42]
  PIN w_mask_in[43]
    DIRECTION INPUT ;
    USE SIGNAL ;
    SHAPE ABUTMENT ;
    PORT
      LAYER M4 ;
      RECT 0.000 18.528 0.024 18.552 ;
    END
  END w_mask_in[43]
  PIN w_mask_in[44]
    DIRECTION INPUT ;
    USE SIGNAL ;
    SHAPE ABUTMENT ;
    PORT
      LAYER M4 ;
      RECT 0.000 18.624 0.024 18.648 ;
    END
  END w_mask_in[44]
  PIN w_mask_in[45]
    DIRECTION INPUT ;
    USE SIGNAL ;
    SHAPE ABUTMENT ;
    PORT
      LAYER M4 ;
      RECT 0.000 18.720 0.024 18.744 ;
    END
  END w_mask_in[45]
  PIN w_mask_in[46]
    DIRECTION INPUT ;
    USE SIGNAL ;
    SHAPE ABUTMENT ;
    PORT
      LAYER M4 ;
      RECT 0.000 18.816 0.024 18.840 ;
    END
  END w_mask_in[46]
  PIN w_mask_in[47]
    DIRECTION INPUT ;
    USE SIGNAL ;
    SHAPE ABUTMENT ;
    PORT
      LAYER M4 ;
      RECT 0.000 18.912 0.024 18.936 ;
    END
  END w_mask_in[47]
  PIN w_mask_in[48]
    DIRECTION INPUT ;
    USE SIGNAL ;
    SHAPE ABUTMENT ;
    PORT
      LAYER M4 ;
      RECT 0.000 19.008 0.024 19.032 ;
    END
  END w_mask_in[48]
  PIN w_mask_in[49]
    DIRECTION INPUT ;
    USE SIGNAL ;
    SHAPE ABUTMENT ;
    PORT
      LAYER M4 ;
      RECT 0.000 19.104 0.024 19.128 ;
    END
  END w_mask_in[49]
  PIN w_mask_in[50]
    DIRECTION INPUT ;
    USE SIGNAL ;
    SHAPE ABUTMENT ;
    PORT
      LAYER M4 ;
      RECT 0.000 19.200 0.024 19.224 ;
    END
  END w_mask_in[50]
  PIN w_mask_in[51]
    DIRECTION INPUT ;
    USE SIGNAL ;
    SHAPE ABUTMENT ;
    PORT
      LAYER M4 ;
      RECT 0.000 19.296 0.024 19.320 ;
    END
  END w_mask_in[51]
  PIN w_mask_in[52]
    DIRECTION INPUT ;
    USE SIGNAL ;
    SHAPE ABUTMENT ;
    PORT
      LAYER M4 ;
      RECT 0.000 19.392 0.024 19.416 ;
    END
  END w_mask_in[52]
  PIN w_mask_in[53]
    DIRECTION INPUT ;
    USE SIGNAL ;
    SHAPE ABUTMENT ;
    PORT
      LAYER M4 ;
      RECT 0.000 19.488 0.024 19.512 ;
    END
  END w_mask_in[53]
  PIN w_mask_in[54]
    DIRECTION INPUT ;
    USE SIGNAL ;
    SHAPE ABUTMENT ;
    PORT
      LAYER M4 ;
      RECT 0.000 19.584 0.024 19.608 ;
    END
  END w_mask_in[54]
  PIN w_mask_in[55]
    DIRECTION INPUT ;
    USE SIGNAL ;
    SHAPE ABUTMENT ;
    PORT
      LAYER M4 ;
      RECT 0.000 19.680 0.024 19.704 ;
    END
  END w_mask_in[55]
  PIN w_mask_in[56]
    DIRECTION INPUT ;
    USE SIGNAL ;
    SHAPE ABUTMENT ;
    PORT
      LAYER M4 ;
      RECT 0.000 19.776 0.024 19.800 ;
    END
  END w_mask_in[56]
  PIN w_mask_in[57]
    DIRECTION INPUT ;
    USE SIGNAL ;
    SHAPE ABUTMENT ;
    PORT
      LAYER M4 ;
      RECT 0.000 19.872 0.024 19.896 ;
    END
  END w_mask_in[57]
  PIN w_mask_in[58]
    DIRECTION INPUT ;
    USE SIGNAL ;
    SHAPE ABUTMENT ;
    PORT
      LAYER M4 ;
      RECT 0.000 19.968 0.024 19.992 ;
    END
  END w_mask_in[58]
  PIN w_mask_in[59]
    DIRECTION INPUT ;
    USE SIGNAL ;
    SHAPE ABUTMENT ;
    PORT
      LAYER M4 ;
      RECT 0.000 20.064 0.024 20.088 ;
    END
  END w_mask_in[59]
  PIN w_mask_in[60]
    DIRECTION INPUT ;
    USE SIGNAL ;
    SHAPE ABUTMENT ;
    PORT
      LAYER M4 ;
      RECT 0.000 20.160 0.024 20.184 ;
    END
  END w_mask_in[60]
  PIN w_mask_in[61]
    DIRECTION INPUT ;
    USE SIGNAL ;
    SHAPE ABUTMENT ;
    PORT
      LAYER M4 ;
      RECT 0.000 20.256 0.024 20.280 ;
    END
  END w_mask_in[61]
  PIN w_mask_in[62]
    DIRECTION INPUT ;
    USE SIGNAL ;
    SHAPE ABUTMENT ;
    PORT
      LAYER M4 ;
      RECT 0.000 20.352 0.024 20.376 ;
    END
  END w_mask_in[62]
  PIN w_mask_in[63]
    DIRECTION INPUT ;
    USE SIGNAL ;
    SHAPE ABUTMENT ;
    PORT
      LAYER M4 ;
      RECT 0.000 20.448 0.024 20.472 ;
    END
  END w_mask_in[63]
  PIN w_mask_in[64]
    DIRECTION INPUT ;
    USE SIGNAL ;
    SHAPE ABUTMENT ;
    PORT
      LAYER M4 ;
      RECT 0.000 20.544 0.024 20.568 ;
    END
  END w_mask_in[64]
  PIN w_mask_in[65]
    DIRECTION INPUT ;
    USE SIGNAL ;
    SHAPE ABUTMENT ;
    PORT
      LAYER M4 ;
      RECT 0.000 20.640 0.024 20.664 ;
    END
  END w_mask_in[65]
  PIN w_mask_in[66]
    DIRECTION INPUT ;
    USE SIGNAL ;
    SHAPE ABUTMENT ;
    PORT
      LAYER M4 ;
      RECT 0.000 20.736 0.024 20.760 ;
    END
  END w_mask_in[66]
  PIN w_mask_in[67]
    DIRECTION INPUT ;
    USE SIGNAL ;
    SHAPE ABUTMENT ;
    PORT
      LAYER M4 ;
      RECT 0.000 20.832 0.024 20.856 ;
    END
  END w_mask_in[67]
  PIN w_mask_in[68]
    DIRECTION INPUT ;
    USE SIGNAL ;
    SHAPE ABUTMENT ;
    PORT
      LAYER M4 ;
      RECT 0.000 20.928 0.024 20.952 ;
    END
  END w_mask_in[68]
  PIN w_mask_in[69]
    DIRECTION INPUT ;
    USE SIGNAL ;
    SHAPE ABUTMENT ;
    PORT
      LAYER M4 ;
      RECT 0.000 21.024 0.024 21.048 ;
    END
  END w_mask_in[69]
  PIN w_mask_in[70]
    DIRECTION INPUT ;
    USE SIGNAL ;
    SHAPE ABUTMENT ;
    PORT
      LAYER M4 ;
      RECT 0.000 21.120 0.024 21.144 ;
    END
  END w_mask_in[70]
  PIN w_mask_in[71]
    DIRECTION INPUT ;
    USE SIGNAL ;
    SHAPE ABUTMENT ;
    PORT
      LAYER M4 ;
      RECT 0.000 21.216 0.024 21.240 ;
    END
  END w_mask_in[71]
  PIN w_mask_in[72]
    DIRECTION INPUT ;
    USE SIGNAL ;
    SHAPE ABUTMENT ;
    PORT
      LAYER M4 ;
      RECT 0.000 21.312 0.024 21.336 ;
    END
  END w_mask_in[72]
  PIN w_mask_in[73]
    DIRECTION INPUT ;
    USE SIGNAL ;
    SHAPE ABUTMENT ;
    PORT
      LAYER M4 ;
      RECT 0.000 21.408 0.024 21.432 ;
    END
  END w_mask_in[73]
  PIN w_mask_in[74]
    DIRECTION INPUT ;
    USE SIGNAL ;
    SHAPE ABUTMENT ;
    PORT
      LAYER M4 ;
      RECT 0.000 21.504 0.024 21.528 ;
    END
  END w_mask_in[74]
  PIN w_mask_in[75]
    DIRECTION INPUT ;
    USE SIGNAL ;
    SHAPE ABUTMENT ;
    PORT
      LAYER M4 ;
      RECT 122.880 0.768 122.904 0.792 ;
    END
  END w_mask_in[75]
  PIN w_mask_in[76]
    DIRECTION INPUT ;
    USE SIGNAL ;
    SHAPE ABUTMENT ;
    PORT
      LAYER M4 ;
      RECT 122.880 0.864 122.904 0.888 ;
    END
  END w_mask_in[76]
  PIN w_mask_in[77]
    DIRECTION INPUT ;
    USE SIGNAL ;
    SHAPE ABUTMENT ;
    PORT
      LAYER M4 ;
      RECT 122.880 0.960 122.904 0.984 ;
    END
  END w_mask_in[77]
  PIN w_mask_in[78]
    DIRECTION INPUT ;
    USE SIGNAL ;
    SHAPE ABUTMENT ;
    PORT
      LAYER M4 ;
      RECT 122.880 1.056 122.904 1.080 ;
    END
  END w_mask_in[78]
  PIN w_mask_in[79]
    DIRECTION INPUT ;
    USE SIGNAL ;
    SHAPE ABUTMENT ;
    PORT
      LAYER M4 ;
      RECT 122.880 1.152 122.904 1.176 ;
    END
  END w_mask_in[79]
  PIN w_mask_in[80]
    DIRECTION INPUT ;
    USE SIGNAL ;
    SHAPE ABUTMENT ;
    PORT
      LAYER M4 ;
      RECT 122.880 1.248 122.904 1.272 ;
    END
  END w_mask_in[80]
  PIN w_mask_in[81]
    DIRECTION INPUT ;
    USE SIGNAL ;
    SHAPE ABUTMENT ;
    PORT
      LAYER M4 ;
      RECT 122.880 1.344 122.904 1.368 ;
    END
  END w_mask_in[81]
  PIN w_mask_in[82]
    DIRECTION INPUT ;
    USE SIGNAL ;
    SHAPE ABUTMENT ;
    PORT
      LAYER M4 ;
      RECT 122.880 1.440 122.904 1.464 ;
    END
  END w_mask_in[82]
  PIN w_mask_in[83]
    DIRECTION INPUT ;
    USE SIGNAL ;
    SHAPE ABUTMENT ;
    PORT
      LAYER M4 ;
      RECT 122.880 1.536 122.904 1.560 ;
    END
  END w_mask_in[83]
  PIN w_mask_in[84]
    DIRECTION INPUT ;
    USE SIGNAL ;
    SHAPE ABUTMENT ;
    PORT
      LAYER M4 ;
      RECT 122.880 1.632 122.904 1.656 ;
    END
  END w_mask_in[84]
  PIN w_mask_in[85]
    DIRECTION INPUT ;
    USE SIGNAL ;
    SHAPE ABUTMENT ;
    PORT
      LAYER M4 ;
      RECT 122.880 1.728 122.904 1.752 ;
    END
  END w_mask_in[85]
  PIN w_mask_in[86]
    DIRECTION INPUT ;
    USE SIGNAL ;
    SHAPE ABUTMENT ;
    PORT
      LAYER M4 ;
      RECT 122.880 1.824 122.904 1.848 ;
    END
  END w_mask_in[86]
  PIN w_mask_in[87]
    DIRECTION INPUT ;
    USE SIGNAL ;
    SHAPE ABUTMENT ;
    PORT
      LAYER M4 ;
      RECT 122.880 1.920 122.904 1.944 ;
    END
  END w_mask_in[87]
  PIN w_mask_in[88]
    DIRECTION INPUT ;
    USE SIGNAL ;
    SHAPE ABUTMENT ;
    PORT
      LAYER M4 ;
      RECT 122.880 2.016 122.904 2.040 ;
    END
  END w_mask_in[88]
  PIN w_mask_in[89]
    DIRECTION INPUT ;
    USE SIGNAL ;
    SHAPE ABUTMENT ;
    PORT
      LAYER M4 ;
      RECT 122.880 2.112 122.904 2.136 ;
    END
  END w_mask_in[89]
  PIN w_mask_in[90]
    DIRECTION INPUT ;
    USE SIGNAL ;
    SHAPE ABUTMENT ;
    PORT
      LAYER M4 ;
      RECT 122.880 2.208 122.904 2.232 ;
    END
  END w_mask_in[90]
  PIN w_mask_in[91]
    DIRECTION INPUT ;
    USE SIGNAL ;
    SHAPE ABUTMENT ;
    PORT
      LAYER M4 ;
      RECT 122.880 2.304 122.904 2.328 ;
    END
  END w_mask_in[91]
  PIN w_mask_in[92]
    DIRECTION INPUT ;
    USE SIGNAL ;
    SHAPE ABUTMENT ;
    PORT
      LAYER M4 ;
      RECT 122.880 2.400 122.904 2.424 ;
    END
  END w_mask_in[92]
  PIN w_mask_in[93]
    DIRECTION INPUT ;
    USE SIGNAL ;
    SHAPE ABUTMENT ;
    PORT
      LAYER M4 ;
      RECT 122.880 2.496 122.904 2.520 ;
    END
  END w_mask_in[93]
  PIN w_mask_in[94]
    DIRECTION INPUT ;
    USE SIGNAL ;
    SHAPE ABUTMENT ;
    PORT
      LAYER M4 ;
      RECT 122.880 2.592 122.904 2.616 ;
    END
  END w_mask_in[94]
  PIN w_mask_in[95]
    DIRECTION INPUT ;
    USE SIGNAL ;
    SHAPE ABUTMENT ;
    PORT
      LAYER M4 ;
      RECT 122.880 2.688 122.904 2.712 ;
    END
  END w_mask_in[95]
  PIN w_mask_in[96]
    DIRECTION INPUT ;
    USE SIGNAL ;
    SHAPE ABUTMENT ;
    PORT
      LAYER M4 ;
      RECT 122.880 2.784 122.904 2.808 ;
    END
  END w_mask_in[96]
  PIN w_mask_in[97]
    DIRECTION INPUT ;
    USE SIGNAL ;
    SHAPE ABUTMENT ;
    PORT
      LAYER M4 ;
      RECT 122.880 2.880 122.904 2.904 ;
    END
  END w_mask_in[97]
  PIN w_mask_in[98]
    DIRECTION INPUT ;
    USE SIGNAL ;
    SHAPE ABUTMENT ;
    PORT
      LAYER M4 ;
      RECT 122.880 2.976 122.904 3.000 ;
    END
  END w_mask_in[98]
  PIN w_mask_in[99]
    DIRECTION INPUT ;
    USE SIGNAL ;
    SHAPE ABUTMENT ;
    PORT
      LAYER M4 ;
      RECT 122.880 3.072 122.904 3.096 ;
    END
  END w_mask_in[99]
  PIN w_mask_in[100]
    DIRECTION INPUT ;
    USE SIGNAL ;
    SHAPE ABUTMENT ;
    PORT
      LAYER M4 ;
      RECT 122.880 3.168 122.904 3.192 ;
    END
  END w_mask_in[100]
  PIN w_mask_in[101]
    DIRECTION INPUT ;
    USE SIGNAL ;
    SHAPE ABUTMENT ;
    PORT
      LAYER M4 ;
      RECT 122.880 3.264 122.904 3.288 ;
    END
  END w_mask_in[101]
  PIN w_mask_in[102]
    DIRECTION INPUT ;
    USE SIGNAL ;
    SHAPE ABUTMENT ;
    PORT
      LAYER M4 ;
      RECT 122.880 3.360 122.904 3.384 ;
    END
  END w_mask_in[102]
  PIN w_mask_in[103]
    DIRECTION INPUT ;
    USE SIGNAL ;
    SHAPE ABUTMENT ;
    PORT
      LAYER M4 ;
      RECT 122.880 3.456 122.904 3.480 ;
    END
  END w_mask_in[103]
  PIN w_mask_in[104]
    DIRECTION INPUT ;
    USE SIGNAL ;
    SHAPE ABUTMENT ;
    PORT
      LAYER M4 ;
      RECT 122.880 3.552 122.904 3.576 ;
    END
  END w_mask_in[104]
  PIN w_mask_in[105]
    DIRECTION INPUT ;
    USE SIGNAL ;
    SHAPE ABUTMENT ;
    PORT
      LAYER M4 ;
      RECT 122.880 3.648 122.904 3.672 ;
    END
  END w_mask_in[105]
  PIN w_mask_in[106]
    DIRECTION INPUT ;
    USE SIGNAL ;
    SHAPE ABUTMENT ;
    PORT
      LAYER M4 ;
      RECT 122.880 3.744 122.904 3.768 ;
    END
  END w_mask_in[106]
  PIN w_mask_in[107]
    DIRECTION INPUT ;
    USE SIGNAL ;
    SHAPE ABUTMENT ;
    PORT
      LAYER M4 ;
      RECT 122.880 3.840 122.904 3.864 ;
    END
  END w_mask_in[107]
  PIN w_mask_in[108]
    DIRECTION INPUT ;
    USE SIGNAL ;
    SHAPE ABUTMENT ;
    PORT
      LAYER M4 ;
      RECT 122.880 3.936 122.904 3.960 ;
    END
  END w_mask_in[108]
  PIN w_mask_in[109]
    DIRECTION INPUT ;
    USE SIGNAL ;
    SHAPE ABUTMENT ;
    PORT
      LAYER M4 ;
      RECT 122.880 4.032 122.904 4.056 ;
    END
  END w_mask_in[109]
  PIN w_mask_in[110]
    DIRECTION INPUT ;
    USE SIGNAL ;
    SHAPE ABUTMENT ;
    PORT
      LAYER M4 ;
      RECT 122.880 4.128 122.904 4.152 ;
    END
  END w_mask_in[110]
  PIN w_mask_in[111]
    DIRECTION INPUT ;
    USE SIGNAL ;
    SHAPE ABUTMENT ;
    PORT
      LAYER M4 ;
      RECT 122.880 4.224 122.904 4.248 ;
    END
  END w_mask_in[111]
  PIN w_mask_in[112]
    DIRECTION INPUT ;
    USE SIGNAL ;
    SHAPE ABUTMENT ;
    PORT
      LAYER M4 ;
      RECT 122.880 4.320 122.904 4.344 ;
    END
  END w_mask_in[112]
  PIN w_mask_in[113]
    DIRECTION INPUT ;
    USE SIGNAL ;
    SHAPE ABUTMENT ;
    PORT
      LAYER M4 ;
      RECT 122.880 4.416 122.904 4.440 ;
    END
  END w_mask_in[113]
  PIN w_mask_in[114]
    DIRECTION INPUT ;
    USE SIGNAL ;
    SHAPE ABUTMENT ;
    PORT
      LAYER M4 ;
      RECT 122.880 4.512 122.904 4.536 ;
    END
  END w_mask_in[114]
  PIN w_mask_in[115]
    DIRECTION INPUT ;
    USE SIGNAL ;
    SHAPE ABUTMENT ;
    PORT
      LAYER M4 ;
      RECT 122.880 4.608 122.904 4.632 ;
    END
  END w_mask_in[115]
  PIN w_mask_in[116]
    DIRECTION INPUT ;
    USE SIGNAL ;
    SHAPE ABUTMENT ;
    PORT
      LAYER M4 ;
      RECT 122.880 4.704 122.904 4.728 ;
    END
  END w_mask_in[116]
  PIN w_mask_in[117]
    DIRECTION INPUT ;
    USE SIGNAL ;
    SHAPE ABUTMENT ;
    PORT
      LAYER M4 ;
      RECT 122.880 4.800 122.904 4.824 ;
    END
  END w_mask_in[117]
  PIN w_mask_in[118]
    DIRECTION INPUT ;
    USE SIGNAL ;
    SHAPE ABUTMENT ;
    PORT
      LAYER M4 ;
      RECT 122.880 4.896 122.904 4.920 ;
    END
  END w_mask_in[118]
  PIN w_mask_in[119]
    DIRECTION INPUT ;
    USE SIGNAL ;
    SHAPE ABUTMENT ;
    PORT
      LAYER M4 ;
      RECT 122.880 4.992 122.904 5.016 ;
    END
  END w_mask_in[119]
  PIN w_mask_in[120]
    DIRECTION INPUT ;
    USE SIGNAL ;
    SHAPE ABUTMENT ;
    PORT
      LAYER M4 ;
      RECT 122.880 5.088 122.904 5.112 ;
    END
  END w_mask_in[120]
  PIN w_mask_in[121]
    DIRECTION INPUT ;
    USE SIGNAL ;
    SHAPE ABUTMENT ;
    PORT
      LAYER M4 ;
      RECT 122.880 5.184 122.904 5.208 ;
    END
  END w_mask_in[121]
  PIN w_mask_in[122]
    DIRECTION INPUT ;
    USE SIGNAL ;
    SHAPE ABUTMENT ;
    PORT
      LAYER M4 ;
      RECT 122.880 5.280 122.904 5.304 ;
    END
  END w_mask_in[122]
  PIN w_mask_in[123]
    DIRECTION INPUT ;
    USE SIGNAL ;
    SHAPE ABUTMENT ;
    PORT
      LAYER M4 ;
      RECT 122.880 5.376 122.904 5.400 ;
    END
  END w_mask_in[123]
  PIN w_mask_in[124]
    DIRECTION INPUT ;
    USE SIGNAL ;
    SHAPE ABUTMENT ;
    PORT
      LAYER M4 ;
      RECT 122.880 5.472 122.904 5.496 ;
    END
  END w_mask_in[124]
  PIN w_mask_in[125]
    DIRECTION INPUT ;
    USE SIGNAL ;
    SHAPE ABUTMENT ;
    PORT
      LAYER M4 ;
      RECT 122.880 5.568 122.904 5.592 ;
    END
  END w_mask_in[125]
  PIN w_mask_in[126]
    DIRECTION INPUT ;
    USE SIGNAL ;
    SHAPE ABUTMENT ;
    PORT
      LAYER M4 ;
      RECT 122.880 5.664 122.904 5.688 ;
    END
  END w_mask_in[126]
  PIN w_mask_in[127]
    DIRECTION INPUT ;
    USE SIGNAL ;
    SHAPE ABUTMENT ;
    PORT
      LAYER M4 ;
      RECT 122.880 5.760 122.904 5.784 ;
    END
  END w_mask_in[127]
  PIN rd_out[0]
    DIRECTION OUTPUT ;
    USE SIGNAL ;
    SHAPE ABUTMENT ;
    PORT
      LAYER M4 ;
      RECT 122.880 5.856 122.904 5.880 ;
    END
  END rd_out[0]
  PIN rd_out[1]
    DIRECTION OUTPUT ;
    USE SIGNAL ;
    SHAPE ABUTMENT ;
    PORT
      LAYER M4 ;
      RECT 122.880 5.952 122.904 5.976 ;
    END
  END rd_out[1]
  PIN rd_out[2]
    DIRECTION OUTPUT ;
    USE SIGNAL ;
    SHAPE ABUTMENT ;
    PORT
      LAYER M4 ;
      RECT 122.880 6.048 122.904 6.072 ;
    END
  END rd_out[2]
  PIN rd_out[3]
    DIRECTION OUTPUT ;
    USE SIGNAL ;
    SHAPE ABUTMENT ;
    PORT
      LAYER M4 ;
      RECT 122.880 6.144 122.904 6.168 ;
    END
  END rd_out[3]
  PIN rd_out[4]
    DIRECTION OUTPUT ;
    USE SIGNAL ;
    SHAPE ABUTMENT ;
    PORT
      LAYER M4 ;
      RECT 122.880 6.240 122.904 6.264 ;
    END
  END rd_out[4]
  PIN rd_out[5]
    DIRECTION OUTPUT ;
    USE SIGNAL ;
    SHAPE ABUTMENT ;
    PORT
      LAYER M4 ;
      RECT 122.880 6.336 122.904 6.360 ;
    END
  END rd_out[5]
  PIN rd_out[6]
    DIRECTION OUTPUT ;
    USE SIGNAL ;
    SHAPE ABUTMENT ;
    PORT
      LAYER M4 ;
      RECT 122.880 6.432 122.904 6.456 ;
    END
  END rd_out[6]
  PIN rd_out[7]
    DIRECTION OUTPUT ;
    USE SIGNAL ;
    SHAPE ABUTMENT ;
    PORT
      LAYER M4 ;
      RECT 122.880 6.528 122.904 6.552 ;
    END
  END rd_out[7]
  PIN rd_out[8]
    DIRECTION OUTPUT ;
    USE SIGNAL ;
    SHAPE ABUTMENT ;
    PORT
      LAYER M4 ;
      RECT 122.880 6.624 122.904 6.648 ;
    END
  END rd_out[8]
  PIN rd_out[9]
    DIRECTION OUTPUT ;
    USE SIGNAL ;
    SHAPE ABUTMENT ;
    PORT
      LAYER M4 ;
      RECT 122.880 6.720 122.904 6.744 ;
    END
  END rd_out[9]
  PIN rd_out[10]
    DIRECTION OUTPUT ;
    USE SIGNAL ;
    SHAPE ABUTMENT ;
    PORT
      LAYER M4 ;
      RECT 122.880 6.816 122.904 6.840 ;
    END
  END rd_out[10]
  PIN rd_out[11]
    DIRECTION OUTPUT ;
    USE SIGNAL ;
    SHAPE ABUTMENT ;
    PORT
      LAYER M4 ;
      RECT 122.880 6.912 122.904 6.936 ;
    END
  END rd_out[11]
  PIN rd_out[12]
    DIRECTION OUTPUT ;
    USE SIGNAL ;
    SHAPE ABUTMENT ;
    PORT
      LAYER M4 ;
      RECT 122.880 7.008 122.904 7.032 ;
    END
  END rd_out[12]
  PIN rd_out[13]
    DIRECTION OUTPUT ;
    USE SIGNAL ;
    SHAPE ABUTMENT ;
    PORT
      LAYER M4 ;
      RECT 122.880 7.104 122.904 7.128 ;
    END
  END rd_out[13]
  PIN rd_out[14]
    DIRECTION OUTPUT ;
    USE SIGNAL ;
    SHAPE ABUTMENT ;
    PORT
      LAYER M4 ;
      RECT 122.880 7.200 122.904 7.224 ;
    END
  END rd_out[14]
  PIN rd_out[15]
    DIRECTION OUTPUT ;
    USE SIGNAL ;
    SHAPE ABUTMENT ;
    PORT
      LAYER M4 ;
      RECT 122.880 7.296 122.904 7.320 ;
    END
  END rd_out[15]
  PIN rd_out[16]
    DIRECTION OUTPUT ;
    USE SIGNAL ;
    SHAPE ABUTMENT ;
    PORT
      LAYER M4 ;
      RECT 122.880 7.392 122.904 7.416 ;
    END
  END rd_out[16]
  PIN rd_out[17]
    DIRECTION OUTPUT ;
    USE SIGNAL ;
    SHAPE ABUTMENT ;
    PORT
      LAYER M4 ;
      RECT 122.880 7.488 122.904 7.512 ;
    END
  END rd_out[17]
  PIN rd_out[18]
    DIRECTION OUTPUT ;
    USE SIGNAL ;
    SHAPE ABUTMENT ;
    PORT
      LAYER M4 ;
      RECT 122.880 7.584 122.904 7.608 ;
    END
  END rd_out[18]
  PIN rd_out[19]
    DIRECTION OUTPUT ;
    USE SIGNAL ;
    SHAPE ABUTMENT ;
    PORT
      LAYER M4 ;
      RECT 122.880 7.680 122.904 7.704 ;
    END
  END rd_out[19]
  PIN rd_out[20]
    DIRECTION OUTPUT ;
    USE SIGNAL ;
    SHAPE ABUTMENT ;
    PORT
      LAYER M4 ;
      RECT 122.880 7.776 122.904 7.800 ;
    END
  END rd_out[20]
  PIN rd_out[21]
    DIRECTION OUTPUT ;
    USE SIGNAL ;
    SHAPE ABUTMENT ;
    PORT
      LAYER M4 ;
      RECT 122.880 7.872 122.904 7.896 ;
    END
  END rd_out[21]
  PIN rd_out[22]
    DIRECTION OUTPUT ;
    USE SIGNAL ;
    SHAPE ABUTMENT ;
    PORT
      LAYER M4 ;
      RECT 122.880 7.968 122.904 7.992 ;
    END
  END rd_out[22]
  PIN rd_out[23]
    DIRECTION OUTPUT ;
    USE SIGNAL ;
    SHAPE ABUTMENT ;
    PORT
      LAYER M4 ;
      RECT 122.880 8.064 122.904 8.088 ;
    END
  END rd_out[23]
  PIN rd_out[24]
    DIRECTION OUTPUT ;
    USE SIGNAL ;
    SHAPE ABUTMENT ;
    PORT
      LAYER M4 ;
      RECT 122.880 8.160 122.904 8.184 ;
    END
  END rd_out[24]
  PIN rd_out[25]
    DIRECTION OUTPUT ;
    USE SIGNAL ;
    SHAPE ABUTMENT ;
    PORT
      LAYER M4 ;
      RECT 122.880 8.256 122.904 8.280 ;
    END
  END rd_out[25]
  PIN rd_out[26]
    DIRECTION OUTPUT ;
    USE SIGNAL ;
    SHAPE ABUTMENT ;
    PORT
      LAYER M4 ;
      RECT 122.880 8.352 122.904 8.376 ;
    END
  END rd_out[26]
  PIN rd_out[27]
    DIRECTION OUTPUT ;
    USE SIGNAL ;
    SHAPE ABUTMENT ;
    PORT
      LAYER M4 ;
      RECT 122.880 8.448 122.904 8.472 ;
    END
  END rd_out[27]
  PIN rd_out[28]
    DIRECTION OUTPUT ;
    USE SIGNAL ;
    SHAPE ABUTMENT ;
    PORT
      LAYER M4 ;
      RECT 122.880 8.544 122.904 8.568 ;
    END
  END rd_out[28]
  PIN rd_out[29]
    DIRECTION OUTPUT ;
    USE SIGNAL ;
    SHAPE ABUTMENT ;
    PORT
      LAYER M4 ;
      RECT 122.880 8.640 122.904 8.664 ;
    END
  END rd_out[29]
  PIN rd_out[30]
    DIRECTION OUTPUT ;
    USE SIGNAL ;
    SHAPE ABUTMENT ;
    PORT
      LAYER M4 ;
      RECT 122.880 8.736 122.904 8.760 ;
    END
  END rd_out[30]
  PIN rd_out[31]
    DIRECTION OUTPUT ;
    USE SIGNAL ;
    SHAPE ABUTMENT ;
    PORT
      LAYER M4 ;
      RECT 122.880 8.832 122.904 8.856 ;
    END
  END rd_out[31]
  PIN rd_out[32]
    DIRECTION OUTPUT ;
    USE SIGNAL ;
    SHAPE ABUTMENT ;
    PORT
      LAYER M4 ;
      RECT 122.880 8.928 122.904 8.952 ;
    END
  END rd_out[32]
  PIN rd_out[33]
    DIRECTION OUTPUT ;
    USE SIGNAL ;
    SHAPE ABUTMENT ;
    PORT
      LAYER M4 ;
      RECT 122.880 9.024 122.904 9.048 ;
    END
  END rd_out[33]
  PIN rd_out[34]
    DIRECTION OUTPUT ;
    USE SIGNAL ;
    SHAPE ABUTMENT ;
    PORT
      LAYER M4 ;
      RECT 122.880 9.120 122.904 9.144 ;
    END
  END rd_out[34]
  PIN rd_out[35]
    DIRECTION OUTPUT ;
    USE SIGNAL ;
    SHAPE ABUTMENT ;
    PORT
      LAYER M4 ;
      RECT 122.880 9.216 122.904 9.240 ;
    END
  END rd_out[35]
  PIN rd_out[36]
    DIRECTION OUTPUT ;
    USE SIGNAL ;
    SHAPE ABUTMENT ;
    PORT
      LAYER M4 ;
      RECT 122.880 9.312 122.904 9.336 ;
    END
  END rd_out[36]
  PIN rd_out[37]
    DIRECTION OUTPUT ;
    USE SIGNAL ;
    SHAPE ABUTMENT ;
    PORT
      LAYER M4 ;
      RECT 122.880 9.408 122.904 9.432 ;
    END
  END rd_out[37]
  PIN rd_out[38]
    DIRECTION OUTPUT ;
    USE SIGNAL ;
    SHAPE ABUTMENT ;
    PORT
      LAYER M4 ;
      RECT 122.880 9.504 122.904 9.528 ;
    END
  END rd_out[38]
  PIN rd_out[39]
    DIRECTION OUTPUT ;
    USE SIGNAL ;
    SHAPE ABUTMENT ;
    PORT
      LAYER M4 ;
      RECT 122.880 9.600 122.904 9.624 ;
    END
  END rd_out[39]
  PIN rd_out[40]
    DIRECTION OUTPUT ;
    USE SIGNAL ;
    SHAPE ABUTMENT ;
    PORT
      LAYER M4 ;
      RECT 122.880 9.696 122.904 9.720 ;
    END
  END rd_out[40]
  PIN rd_out[41]
    DIRECTION OUTPUT ;
    USE SIGNAL ;
    SHAPE ABUTMENT ;
    PORT
      LAYER M4 ;
      RECT 122.880 9.792 122.904 9.816 ;
    END
  END rd_out[41]
  PIN rd_out[42]
    DIRECTION OUTPUT ;
    USE SIGNAL ;
    SHAPE ABUTMENT ;
    PORT
      LAYER M4 ;
      RECT 122.880 9.888 122.904 9.912 ;
    END
  END rd_out[42]
  PIN rd_out[43]
    DIRECTION OUTPUT ;
    USE SIGNAL ;
    SHAPE ABUTMENT ;
    PORT
      LAYER M4 ;
      RECT 122.880 9.984 122.904 10.008 ;
    END
  END rd_out[43]
  PIN rd_out[44]
    DIRECTION OUTPUT ;
    USE SIGNAL ;
    SHAPE ABUTMENT ;
    PORT
      LAYER M4 ;
      RECT 122.880 10.080 122.904 10.104 ;
    END
  END rd_out[44]
  PIN rd_out[45]
    DIRECTION OUTPUT ;
    USE SIGNAL ;
    SHAPE ABUTMENT ;
    PORT
      LAYER M4 ;
      RECT 122.880 10.176 122.904 10.200 ;
    END
  END rd_out[45]
  PIN rd_out[46]
    DIRECTION OUTPUT ;
    USE SIGNAL ;
    SHAPE ABUTMENT ;
    PORT
      LAYER M4 ;
      RECT 122.880 10.272 122.904 10.296 ;
    END
  END rd_out[46]
  PIN rd_out[47]
    DIRECTION OUTPUT ;
    USE SIGNAL ;
    SHAPE ABUTMENT ;
    PORT
      LAYER M4 ;
      RECT 122.880 10.368 122.904 10.392 ;
    END
  END rd_out[47]
  PIN rd_out[48]
    DIRECTION OUTPUT ;
    USE SIGNAL ;
    SHAPE ABUTMENT ;
    PORT
      LAYER M4 ;
      RECT 122.880 10.464 122.904 10.488 ;
    END
  END rd_out[48]
  PIN rd_out[49]
    DIRECTION OUTPUT ;
    USE SIGNAL ;
    SHAPE ABUTMENT ;
    PORT
      LAYER M4 ;
      RECT 122.880 10.560 122.904 10.584 ;
    END
  END rd_out[49]
  PIN rd_out[50]
    DIRECTION OUTPUT ;
    USE SIGNAL ;
    SHAPE ABUTMENT ;
    PORT
      LAYER M4 ;
      RECT 122.880 10.656 122.904 10.680 ;
    END
  END rd_out[50]
  PIN rd_out[51]
    DIRECTION OUTPUT ;
    USE SIGNAL ;
    SHAPE ABUTMENT ;
    PORT
      LAYER M4 ;
      RECT 122.880 10.752 122.904 10.776 ;
    END
  END rd_out[51]
  PIN rd_out[52]
    DIRECTION OUTPUT ;
    USE SIGNAL ;
    SHAPE ABUTMENT ;
    PORT
      LAYER M4 ;
      RECT 122.880 10.848 122.904 10.872 ;
    END
  END rd_out[52]
  PIN rd_out[53]
    DIRECTION OUTPUT ;
    USE SIGNAL ;
    SHAPE ABUTMENT ;
    PORT
      LAYER M4 ;
      RECT 122.880 10.944 122.904 10.968 ;
    END
  END rd_out[53]
  PIN rd_out[54]
    DIRECTION OUTPUT ;
    USE SIGNAL ;
    SHAPE ABUTMENT ;
    PORT
      LAYER M4 ;
      RECT 122.880 11.040 122.904 11.064 ;
    END
  END rd_out[54]
  PIN rd_out[55]
    DIRECTION OUTPUT ;
    USE SIGNAL ;
    SHAPE ABUTMENT ;
    PORT
      LAYER M4 ;
      RECT 122.880 11.136 122.904 11.160 ;
    END
  END rd_out[55]
  PIN rd_out[56]
    DIRECTION OUTPUT ;
    USE SIGNAL ;
    SHAPE ABUTMENT ;
    PORT
      LAYER M4 ;
      RECT 122.880 11.232 122.904 11.256 ;
    END
  END rd_out[56]
  PIN rd_out[57]
    DIRECTION OUTPUT ;
    USE SIGNAL ;
    SHAPE ABUTMENT ;
    PORT
      LAYER M4 ;
      RECT 122.880 11.328 122.904 11.352 ;
    END
  END rd_out[57]
  PIN rd_out[58]
    DIRECTION OUTPUT ;
    USE SIGNAL ;
    SHAPE ABUTMENT ;
    PORT
      LAYER M4 ;
      RECT 122.880 11.424 122.904 11.448 ;
    END
  END rd_out[58]
  PIN rd_out[59]
    DIRECTION OUTPUT ;
    USE SIGNAL ;
    SHAPE ABUTMENT ;
    PORT
      LAYER M4 ;
      RECT 122.880 11.520 122.904 11.544 ;
    END
  END rd_out[59]
  PIN rd_out[60]
    DIRECTION OUTPUT ;
    USE SIGNAL ;
    SHAPE ABUTMENT ;
    PORT
      LAYER M4 ;
      RECT 122.880 11.616 122.904 11.640 ;
    END
  END rd_out[60]
  PIN rd_out[61]
    DIRECTION OUTPUT ;
    USE SIGNAL ;
    SHAPE ABUTMENT ;
    PORT
      LAYER M4 ;
      RECT 122.880 11.712 122.904 11.736 ;
    END
  END rd_out[61]
  PIN rd_out[62]
    DIRECTION OUTPUT ;
    USE SIGNAL ;
    SHAPE ABUTMENT ;
    PORT
      LAYER M4 ;
      RECT 122.880 11.808 122.904 11.832 ;
    END
  END rd_out[62]
  PIN rd_out[63]
    DIRECTION OUTPUT ;
    USE SIGNAL ;
    SHAPE ABUTMENT ;
    PORT
      LAYER M4 ;
      RECT 122.880 11.904 122.904 11.928 ;
    END
  END rd_out[63]
  PIN rd_out[64]
    DIRECTION OUTPUT ;
    USE SIGNAL ;
    SHAPE ABUTMENT ;
    PORT
      LAYER M4 ;
      RECT 122.880 12.000 122.904 12.024 ;
    END
  END rd_out[64]
  PIN rd_out[65]
    DIRECTION OUTPUT ;
    USE SIGNAL ;
    SHAPE ABUTMENT ;
    PORT
      LAYER M4 ;
      RECT 122.880 12.096 122.904 12.120 ;
    END
  END rd_out[65]
  PIN rd_out[66]
    DIRECTION OUTPUT ;
    USE SIGNAL ;
    SHAPE ABUTMENT ;
    PORT
      LAYER M4 ;
      RECT 122.880 12.192 122.904 12.216 ;
    END
  END rd_out[66]
  PIN rd_out[67]
    DIRECTION OUTPUT ;
    USE SIGNAL ;
    SHAPE ABUTMENT ;
    PORT
      LAYER M4 ;
      RECT 122.880 12.288 122.904 12.312 ;
    END
  END rd_out[67]
  PIN rd_out[68]
    DIRECTION OUTPUT ;
    USE SIGNAL ;
    SHAPE ABUTMENT ;
    PORT
      LAYER M4 ;
      RECT 122.880 12.384 122.904 12.408 ;
    END
  END rd_out[68]
  PIN rd_out[69]
    DIRECTION OUTPUT ;
    USE SIGNAL ;
    SHAPE ABUTMENT ;
    PORT
      LAYER M4 ;
      RECT 122.880 12.480 122.904 12.504 ;
    END
  END rd_out[69]
  PIN rd_out[70]
    DIRECTION OUTPUT ;
    USE SIGNAL ;
    SHAPE ABUTMENT ;
    PORT
      LAYER M4 ;
      RECT 122.880 12.576 122.904 12.600 ;
    END
  END rd_out[70]
  PIN rd_out[71]
    DIRECTION OUTPUT ;
    USE SIGNAL ;
    SHAPE ABUTMENT ;
    PORT
      LAYER M4 ;
      RECT 122.880 12.672 122.904 12.696 ;
    END
  END rd_out[71]
  PIN rd_out[72]
    DIRECTION OUTPUT ;
    USE SIGNAL ;
    SHAPE ABUTMENT ;
    PORT
      LAYER M4 ;
      RECT 122.880 12.768 122.904 12.792 ;
    END
  END rd_out[72]
  PIN rd_out[73]
    DIRECTION OUTPUT ;
    USE SIGNAL ;
    SHAPE ABUTMENT ;
    PORT
      LAYER M4 ;
      RECT 122.880 12.864 122.904 12.888 ;
    END
  END rd_out[73]
  PIN rd_out[74]
    DIRECTION OUTPUT ;
    USE SIGNAL ;
    SHAPE ABUTMENT ;
    PORT
      LAYER M4 ;
      RECT 122.880 12.960 122.904 12.984 ;
    END
  END rd_out[74]
  PIN rd_out[75]
    DIRECTION OUTPUT ;
    USE SIGNAL ;
    SHAPE ABUTMENT ;
    PORT
      LAYER M4 ;
      RECT 122.880 13.056 122.904 13.080 ;
    END
  END rd_out[75]
  PIN rd_out[76]
    DIRECTION OUTPUT ;
    USE SIGNAL ;
    SHAPE ABUTMENT ;
    PORT
      LAYER M4 ;
      RECT 122.880 13.152 122.904 13.176 ;
    END
  END rd_out[76]
  PIN rd_out[77]
    DIRECTION OUTPUT ;
    USE SIGNAL ;
    SHAPE ABUTMENT ;
    PORT
      LAYER M4 ;
      RECT 122.880 13.248 122.904 13.272 ;
    END
  END rd_out[77]
  PIN rd_out[78]
    DIRECTION OUTPUT ;
    USE SIGNAL ;
    SHAPE ABUTMENT ;
    PORT
      LAYER M4 ;
      RECT 122.880 13.344 122.904 13.368 ;
    END
  END rd_out[78]
  PIN rd_out[79]
    DIRECTION OUTPUT ;
    USE SIGNAL ;
    SHAPE ABUTMENT ;
    PORT
      LAYER M4 ;
      RECT 122.880 13.440 122.904 13.464 ;
    END
  END rd_out[79]
  PIN rd_out[80]
    DIRECTION OUTPUT ;
    USE SIGNAL ;
    SHAPE ABUTMENT ;
    PORT
      LAYER M4 ;
      RECT 122.880 13.536 122.904 13.560 ;
    END
  END rd_out[80]
  PIN rd_out[81]
    DIRECTION OUTPUT ;
    USE SIGNAL ;
    SHAPE ABUTMENT ;
    PORT
      LAYER M4 ;
      RECT 122.880 13.632 122.904 13.656 ;
    END
  END rd_out[81]
  PIN rd_out[82]
    DIRECTION OUTPUT ;
    USE SIGNAL ;
    SHAPE ABUTMENT ;
    PORT
      LAYER M4 ;
      RECT 122.880 13.728 122.904 13.752 ;
    END
  END rd_out[82]
  PIN rd_out[83]
    DIRECTION OUTPUT ;
    USE SIGNAL ;
    SHAPE ABUTMENT ;
    PORT
      LAYER M4 ;
      RECT 122.880 13.824 122.904 13.848 ;
    END
  END rd_out[83]
  PIN rd_out[84]
    DIRECTION OUTPUT ;
    USE SIGNAL ;
    SHAPE ABUTMENT ;
    PORT
      LAYER M4 ;
      RECT 122.880 13.920 122.904 13.944 ;
    END
  END rd_out[84]
  PIN rd_out[85]
    DIRECTION OUTPUT ;
    USE SIGNAL ;
    SHAPE ABUTMENT ;
    PORT
      LAYER M4 ;
      RECT 122.880 14.016 122.904 14.040 ;
    END
  END rd_out[85]
  PIN rd_out[86]
    DIRECTION OUTPUT ;
    USE SIGNAL ;
    SHAPE ABUTMENT ;
    PORT
      LAYER M4 ;
      RECT 122.880 14.112 122.904 14.136 ;
    END
  END rd_out[86]
  PIN rd_out[87]
    DIRECTION OUTPUT ;
    USE SIGNAL ;
    SHAPE ABUTMENT ;
    PORT
      LAYER M4 ;
      RECT 122.880 14.208 122.904 14.232 ;
    END
  END rd_out[87]
  PIN rd_out[88]
    DIRECTION OUTPUT ;
    USE SIGNAL ;
    SHAPE ABUTMENT ;
    PORT
      LAYER M4 ;
      RECT 122.880 14.304 122.904 14.328 ;
    END
  END rd_out[88]
  PIN rd_out[89]
    DIRECTION OUTPUT ;
    USE SIGNAL ;
    SHAPE ABUTMENT ;
    PORT
      LAYER M4 ;
      RECT 122.880 14.400 122.904 14.424 ;
    END
  END rd_out[89]
  PIN rd_out[90]
    DIRECTION OUTPUT ;
    USE SIGNAL ;
    SHAPE ABUTMENT ;
    PORT
      LAYER M4 ;
      RECT 122.880 14.496 122.904 14.520 ;
    END
  END rd_out[90]
  PIN rd_out[91]
    DIRECTION OUTPUT ;
    USE SIGNAL ;
    SHAPE ABUTMENT ;
    PORT
      LAYER M4 ;
      RECT 122.880 14.592 122.904 14.616 ;
    END
  END rd_out[91]
  PIN rd_out[92]
    DIRECTION OUTPUT ;
    USE SIGNAL ;
    SHAPE ABUTMENT ;
    PORT
      LAYER M4 ;
      RECT 122.880 14.688 122.904 14.712 ;
    END
  END rd_out[92]
  PIN rd_out[93]
    DIRECTION OUTPUT ;
    USE SIGNAL ;
    SHAPE ABUTMENT ;
    PORT
      LAYER M4 ;
      RECT 122.880 14.784 122.904 14.808 ;
    END
  END rd_out[93]
  PIN rd_out[94]
    DIRECTION OUTPUT ;
    USE SIGNAL ;
    SHAPE ABUTMENT ;
    PORT
      LAYER M4 ;
      RECT 122.880 14.880 122.904 14.904 ;
    END
  END rd_out[94]
  PIN rd_out[95]
    DIRECTION OUTPUT ;
    USE SIGNAL ;
    SHAPE ABUTMENT ;
    PORT
      LAYER M4 ;
      RECT 122.880 14.976 122.904 15.000 ;
    END
  END rd_out[95]
  PIN rd_out[96]
    DIRECTION OUTPUT ;
    USE SIGNAL ;
    SHAPE ABUTMENT ;
    PORT
      LAYER M4 ;
      RECT 122.880 15.072 122.904 15.096 ;
    END
  END rd_out[96]
  PIN rd_out[97]
    DIRECTION OUTPUT ;
    USE SIGNAL ;
    SHAPE ABUTMENT ;
    PORT
      LAYER M4 ;
      RECT 122.880 15.168 122.904 15.192 ;
    END
  END rd_out[97]
  PIN rd_out[98]
    DIRECTION OUTPUT ;
    USE SIGNAL ;
    SHAPE ABUTMENT ;
    PORT
      LAYER M4 ;
      RECT 122.880 15.264 122.904 15.288 ;
    END
  END rd_out[98]
  PIN rd_out[99]
    DIRECTION OUTPUT ;
    USE SIGNAL ;
    SHAPE ABUTMENT ;
    PORT
      LAYER M4 ;
      RECT 122.880 15.360 122.904 15.384 ;
    END
  END rd_out[99]
  PIN rd_out[100]
    DIRECTION OUTPUT ;
    USE SIGNAL ;
    SHAPE ABUTMENT ;
    PORT
      LAYER M4 ;
      RECT 122.880 15.456 122.904 15.480 ;
    END
  END rd_out[100]
  PIN rd_out[101]
    DIRECTION OUTPUT ;
    USE SIGNAL ;
    SHAPE ABUTMENT ;
    PORT
      LAYER M4 ;
      RECT 122.880 15.552 122.904 15.576 ;
    END
  END rd_out[101]
  PIN rd_out[102]
    DIRECTION OUTPUT ;
    USE SIGNAL ;
    SHAPE ABUTMENT ;
    PORT
      LAYER M4 ;
      RECT 122.880 15.648 122.904 15.672 ;
    END
  END rd_out[102]
  PIN rd_out[103]
    DIRECTION OUTPUT ;
    USE SIGNAL ;
    SHAPE ABUTMENT ;
    PORT
      LAYER M4 ;
      RECT 122.880 15.744 122.904 15.768 ;
    END
  END rd_out[103]
  PIN rd_out[104]
    DIRECTION OUTPUT ;
    USE SIGNAL ;
    SHAPE ABUTMENT ;
    PORT
      LAYER M4 ;
      RECT 122.880 15.840 122.904 15.864 ;
    END
  END rd_out[104]
  PIN rd_out[105]
    DIRECTION OUTPUT ;
    USE SIGNAL ;
    SHAPE ABUTMENT ;
    PORT
      LAYER M4 ;
      RECT 122.880 15.936 122.904 15.960 ;
    END
  END rd_out[105]
  PIN rd_out[106]
    DIRECTION OUTPUT ;
    USE SIGNAL ;
    SHAPE ABUTMENT ;
    PORT
      LAYER M4 ;
      RECT 122.880 16.032 122.904 16.056 ;
    END
  END rd_out[106]
  PIN rd_out[107]
    DIRECTION OUTPUT ;
    USE SIGNAL ;
    SHAPE ABUTMENT ;
    PORT
      LAYER M4 ;
      RECT 122.880 16.128 122.904 16.152 ;
    END
  END rd_out[107]
  PIN rd_out[108]
    DIRECTION OUTPUT ;
    USE SIGNAL ;
    SHAPE ABUTMENT ;
    PORT
      LAYER M4 ;
      RECT 122.880 16.224 122.904 16.248 ;
    END
  END rd_out[108]
  PIN rd_out[109]
    DIRECTION OUTPUT ;
    USE SIGNAL ;
    SHAPE ABUTMENT ;
    PORT
      LAYER M4 ;
      RECT 122.880 16.320 122.904 16.344 ;
    END
  END rd_out[109]
  PIN rd_out[110]
    DIRECTION OUTPUT ;
    USE SIGNAL ;
    SHAPE ABUTMENT ;
    PORT
      LAYER M4 ;
      RECT 122.880 16.416 122.904 16.440 ;
    END
  END rd_out[110]
  PIN rd_out[111]
    DIRECTION OUTPUT ;
    USE SIGNAL ;
    SHAPE ABUTMENT ;
    PORT
      LAYER M4 ;
      RECT 122.880 16.512 122.904 16.536 ;
    END
  END rd_out[111]
  PIN rd_out[112]
    DIRECTION OUTPUT ;
    USE SIGNAL ;
    SHAPE ABUTMENT ;
    PORT
      LAYER M4 ;
      RECT 122.880 16.608 122.904 16.632 ;
    END
  END rd_out[112]
  PIN rd_out[113]
    DIRECTION OUTPUT ;
    USE SIGNAL ;
    SHAPE ABUTMENT ;
    PORT
      LAYER M4 ;
      RECT 122.880 16.704 122.904 16.728 ;
    END
  END rd_out[113]
  PIN rd_out[114]
    DIRECTION OUTPUT ;
    USE SIGNAL ;
    SHAPE ABUTMENT ;
    PORT
      LAYER M4 ;
      RECT 122.880 16.800 122.904 16.824 ;
    END
  END rd_out[114]
  PIN rd_out[115]
    DIRECTION OUTPUT ;
    USE SIGNAL ;
    SHAPE ABUTMENT ;
    PORT
      LAYER M4 ;
      RECT 122.880 16.896 122.904 16.920 ;
    END
  END rd_out[115]
  PIN rd_out[116]
    DIRECTION OUTPUT ;
    USE SIGNAL ;
    SHAPE ABUTMENT ;
    PORT
      LAYER M4 ;
      RECT 122.880 16.992 122.904 17.016 ;
    END
  END rd_out[116]
  PIN rd_out[117]
    DIRECTION OUTPUT ;
    USE SIGNAL ;
    SHAPE ABUTMENT ;
    PORT
      LAYER M4 ;
      RECT 122.880 17.088 122.904 17.112 ;
    END
  END rd_out[117]
  PIN rd_out[118]
    DIRECTION OUTPUT ;
    USE SIGNAL ;
    SHAPE ABUTMENT ;
    PORT
      LAYER M4 ;
      RECT 122.880 17.184 122.904 17.208 ;
    END
  END rd_out[118]
  PIN rd_out[119]
    DIRECTION OUTPUT ;
    USE SIGNAL ;
    SHAPE ABUTMENT ;
    PORT
      LAYER M4 ;
      RECT 122.880 17.280 122.904 17.304 ;
    END
  END rd_out[119]
  PIN rd_out[120]
    DIRECTION OUTPUT ;
    USE SIGNAL ;
    SHAPE ABUTMENT ;
    PORT
      LAYER M4 ;
      RECT 122.880 17.376 122.904 17.400 ;
    END
  END rd_out[120]
  PIN rd_out[121]
    DIRECTION OUTPUT ;
    USE SIGNAL ;
    SHAPE ABUTMENT ;
    PORT
      LAYER M4 ;
      RECT 122.880 17.472 122.904 17.496 ;
    END
  END rd_out[121]
  PIN rd_out[122]
    DIRECTION OUTPUT ;
    USE SIGNAL ;
    SHAPE ABUTMENT ;
    PORT
      LAYER M4 ;
      RECT 122.880 17.568 122.904 17.592 ;
    END
  END rd_out[122]
  PIN rd_out[123]
    DIRECTION OUTPUT ;
    USE SIGNAL ;
    SHAPE ABUTMENT ;
    PORT
      LAYER M4 ;
      RECT 122.880 17.664 122.904 17.688 ;
    END
  END rd_out[123]
  PIN rd_out[124]
    DIRECTION OUTPUT ;
    USE SIGNAL ;
    SHAPE ABUTMENT ;
    PORT
      LAYER M4 ;
      RECT 122.880 17.760 122.904 17.784 ;
    END
  END rd_out[124]
  PIN rd_out[125]
    DIRECTION OUTPUT ;
    USE SIGNAL ;
    SHAPE ABUTMENT ;
    PORT
      LAYER M4 ;
      RECT 122.880 17.856 122.904 17.880 ;
    END
  END rd_out[125]
  PIN rd_out[126]
    DIRECTION OUTPUT ;
    USE SIGNAL ;
    SHAPE ABUTMENT ;
    PORT
      LAYER M4 ;
      RECT 122.880 17.952 122.904 17.976 ;
    END
  END rd_out[126]
  PIN rd_out[127]
    DIRECTION OUTPUT ;
    USE SIGNAL ;
    SHAPE ABUTMENT ;
    PORT
      LAYER M4 ;
      RECT 122.880 18.048 122.904 18.072 ;
    END
  END rd_out[127]
  PIN rr_en[0]
    DIRECTION INPUT ;
    USE SIGNAL ;
    SHAPE ABUTMENT ;
    PORT
      LAYER M4 ;
      RECT 122.880 18.144 122.904 18.168 ;
    END
  END rr_en[0]
  PIN rr_en[1]
    DIRECTION INPUT ;
    USE SIGNAL ;
    SHAPE ABUTMENT ;
    PORT
      LAYER M4 ;
      RECT 122.880 18.240 122.904 18.264 ;
    END
  END rr_en[1]
  PIN rr_addr[0]
    DIRECTION INPUT ;
    USE SIGNAL ;
    SHAPE ABUTMENT ;
    PORT
      LAYER M4 ;
      RECT 122.880 18.336 122.904 18.360 ;
    END
  END rr_addr[0]
  PIN rr_addr[1]
    DIRECTION INPUT ;
    USE SIGNAL ;
    SHAPE ABUTMENT ;
    PORT
      LAYER M4 ;
      RECT 122.880 18.432 122.904 18.456 ;
    END
  END rr_addr[1]
  PIN rr_addr[2]
    DIRECTION INPUT ;
    USE SIGNAL ;
    SHAPE ABUTMENT ;
    PORT
      LAYER M4 ;
      RECT 122.880 18.528 122.904 18.552 ;
    END
  END rr_addr[2]
  PIN rr_addr[3]
    DIRECTION INPUT ;
    USE SIGNAL ;
    SHAPE ABUTMENT ;
    PORT
      LAYER M4 ;
      RECT 122.880 18.624 122.904 18.648 ;
    END
  END rr_addr[3]
  PIN rr_addr[4]
    DIRECTION INPUT ;
    USE SIGNAL ;
    SHAPE ABUTMENT ;
    PORT
      LAYER M4 ;
      RECT 122.880 18.720 122.904 18.744 ;
    END
  END rr_addr[4]
  PIN rr_addr[5]
    DIRECTION INPUT ;
    USE SIGNAL ;
    SHAPE ABUTMENT ;
    PORT
      LAYER M4 ;
      RECT 122.880 18.816 122.904 18.840 ;
    END
  END rr_addr[5]
  PIN rr_addr[6]
    DIRECTION INPUT ;
    USE SIGNAL ;
    SHAPE ABUTMENT ;
    PORT
      LAYER M4 ;
      RECT 122.880 18.912 122.904 18.936 ;
    END
  END rr_addr[6]
  PIN rr_addr[7]
    DIRECTION INPUT ;
    USE SIGNAL ;
    SHAPE ABUTMENT ;
    PORT
      LAYER M4 ;
      RECT 122.880 19.008 122.904 19.032 ;
    END
  END rr_addr[7]
  PIN rr_addr[8]
    DIRECTION INPUT ;
    USE SIGNAL ;
    SHAPE ABUTMENT ;
    PORT
      LAYER M4 ;
      RECT 122.880 19.104 122.904 19.128 ;
    END
  END rr_addr[8]
  PIN rr_addr[9]
    DIRECTION INPUT ;
    USE SIGNAL ;
    SHAPE ABUTMENT ;
    PORT
      LAYER M4 ;
      RECT 122.880 19.200 122.904 19.224 ;
    END
  END rr_addr[9]
  PIN rr_addr[10]
    DIRECTION INPUT ;
    USE SIGNAL ;
    SHAPE ABUTMENT ;
    PORT
      LAYER M4 ;
      RECT 122.880 19.296 122.904 19.320 ;
    END
  END rr_addr[10]
  PIN rr_addr[11]
    DIRECTION INPUT ;
    USE SIGNAL ;
    SHAPE ABUTMENT ;
    PORT
      LAYER M4 ;
      RECT 122.880 19.392 122.904 19.416 ;
    END
  END rr_addr[11]
  PIN rr_addr[12]
    DIRECTION INPUT ;
    USE SIGNAL ;
    SHAPE ABUTMENT ;
    PORT
      LAYER M4 ;
      RECT 122.880 19.488 122.904 19.512 ;
    END
  END rr_addr[12]
  PIN rr_addr[13]
    DIRECTION INPUT ;
    USE SIGNAL ;
    SHAPE ABUTMENT ;
    PORT
      LAYER M4 ;
      RECT 122.880 19.584 122.904 19.608 ;
    END
  END rr_addr[13]
  PIN rr_addr[14]
    DIRECTION INPUT ;
    USE SIGNAL ;
    SHAPE ABUTMENT ;
    PORT
      LAYER M4 ;
      RECT 122.880 19.680 122.904 19.704 ;
    END
  END rr_addr[14]
  PIN rr_addr[15]
    DIRECTION INPUT ;
    USE SIGNAL ;
    SHAPE ABUTMENT ;
    PORT
      LAYER M4 ;
      RECT 122.880 19.776 122.904 19.800 ;
    END
  END rr_addr[15]
  PIN rr_addr[16]
    DIRECTION INPUT ;
    USE SIGNAL ;
    SHAPE ABUTMENT ;
    PORT
      LAYER M4 ;
      RECT 122.880 19.872 122.904 19.896 ;
    END
  END rr_addr[16]
  PIN rr_addr[17]
    DIRECTION INPUT ;
    USE SIGNAL ;
    SHAPE ABUTMENT ;
    PORT
      LAYER M4 ;
      RECT 122.880 19.968 122.904 19.992 ;
    END
  END rr_addr[17]
  PIN cr_en[0]
    DIRECTION INPUT ;
    USE SIGNAL ;
    SHAPE ABUTMENT ;
    PORT
      LAYER M4 ;
      RECT 122.880 20.064 122.904 20.088 ;
    END
  END cr_en[0]
  PIN cr_en[1]
    DIRECTION INPUT ;
    USE SIGNAL ;
    SHAPE ABUTMENT ;
    PORT
      LAYER M4 ;
      RECT 122.880 20.160 122.904 20.184 ;
    END
  END cr_en[1]
  PIN cr_sel[0]
    DIRECTION INPUT ;
    USE SIGNAL ;
    SHAPE ABUTMENT ;
    PORT
      LAYER M4 ;
      RECT 122.880 20.256 122.904 20.280 ;
    END
  END cr_sel[0]
  PIN cr_sel[1]
    DIRECTION INPUT ;
    USE SIGNAL ;
    SHAPE ABUTMENT ;
    PORT
      LAYER M4 ;
      RECT 122.880 20.352 122.904 20.376 ;
    END
  END cr_sel[1]
  PIN cr_sel[2]
    DIRECTION INPUT ;
    USE SIGNAL ;
    SHAPE ABUTMENT ;
    PORT
      LAYER M4 ;
      RECT 122.880 20.448 122.904 20.472 ;
    END
  END cr_sel[2]
  PIN cr_sel[3]
    DIRECTION INPUT ;
    USE SIGNAL ;
    SHAPE ABUTMENT ;
    PORT
      LAYER M4 ;
      RECT 122.880 20.544 122.904 20.568 ;
    END
  END cr_sel[3]
  PIN cr_sel[4]
    DIRECTION INPUT ;
    USE SIGNAL ;
    SHAPE ABUTMENT ;
    PORT
      LAYER M4 ;
      RECT 122.880 20.640 122.904 20.664 ;
    END
  END cr_sel[4]
  PIN cr_sel[5]
    DIRECTION INPUT ;
    USE SIGNAL ;
    SHAPE ABUTMENT ;
    PORT
      LAYER M4 ;
      RECT 122.880 20.736 122.904 20.760 ;
    END
  END cr_sel[5]
  PIN cr_sel[6]
    DIRECTION INPUT ;
    USE SIGNAL ;
    SHAPE ABUTMENT ;
    PORT
      LAYER M4 ;
      RECT 122.880 20.832 122.904 20.856 ;
    END
  END cr_sel[6]
  PIN cr_sel[7]
    DIRECTION INPUT ;
    USE SIGNAL ;
    SHAPE ABUTMENT ;
    PORT
      LAYER M4 ;
      RECT 122.880 20.928 122.904 20.952 ;
    END
  END cr_sel[7]
  PIN cr_sel[8]
    DIRECTION INPUT ;
    USE SIGNAL ;
    SHAPE ABUTMENT ;
    PORT
      LAYER M4 ;
      RECT 122.880 21.024 122.904 21.048 ;
    END
  END cr_sel[8]
  PIN cr_sel[9]
    DIRECTION INPUT ;
    USE SIGNAL ;
    SHAPE ABUTMENT ;
    PORT
      LAYER M4 ;
      RECT 122.880 21.120 122.904 21.144 ;
    END
  END cr_sel[9]
  PIN cr_sel[10]
    DIRECTION INPUT ;
    USE SIGNAL ;
    SHAPE ABUTMENT ;
    PORT
      LAYER M4 ;
      RECT 122.880 21.216 122.904 21.240 ;
    END
  END cr_sel[10]
  PIN cr_sel[11]
    DIRECTION INPUT ;
    USE SIGNAL ;
    SHAPE ABUTMENT ;
    PORT
      LAYER M4 ;
      RECT 122.880 21.312 122.904 21.336 ;
    END
  END cr_sel[11]
  PIN cr_sel[12]
    DIRECTION INPUT ;
    USE SIGNAL ;
    SHAPE ABUTMENT ;
    PORT
      LAYER M4 ;
      RECT 122.880 21.408 122.904 21.432 ;
    END
  END cr_sel[12]
  PIN cr_sel[13]
    DIRECTION INPUT ;
    USE SIGNAL ;
    SHAPE ABUTMENT ;
    PORT
      LAYER M4 ;
      RECT 122.880 21.504 122.904 21.528 ;
    END
  END cr_sel[13]
  PIN VDD
    DIRECTION INOUT ;
    USE POWER ;
    PORT
      LAYER M4 ;
      RECT 0.300 0.384 122.604 0.480 ;
      RECT 0.300 1.152 122.604 1.248 ;
      RECT 0.300 1.920 122.604 2.016 ;
      RECT 0.300 2.688 122.604 2.784 ;
      RECT 0.300 3.456 122.604 3.552 ;
      RECT 0.300 4.224 122.604 4.320 ;
      RECT 0.300 4.992 122.604 5.088 ;
      RECT 0.300 5.760 122.604 5.856 ;
      RECT 0.300 6.528 122.604 6.624 ;
      RECT 0.300 7.296 122.604 7.392 ;
      RECT 0.300 8.064 122.604 8.160 ;
      RECT 0.300 8.832 122.604 8.928 ;
      RECT 0.300 9.600 122.604 9.696 ;
      RECT 0.300 10.368 122.604 10.464 ;
      RECT 0.300 11.136 122.604 11.232 ;
      RECT 0.300 11.904 122.604 12.000 ;
      RECT 0.300 12.672 122.604 12.768 ;
      RECT 0.300 13.440 122.604 13.536 ;
      RECT 0.300 14.208 122.604 14.304 ;
      RECT 0.300 14.976 122.604 15.072 ;
      RECT 0.300 15.744 122.604 15.840 ;
      RECT 0.300 16.512 122.604 16.608 ;
      RECT 0.300 17.280 122.604 17.376 ;
      RECT 0.300 18.048 122.604 18.144 ;
      RECT 0.300 18.816 122.604 18.912 ;
      RECT 0.300 19.584 122.604 19.680 ;
      RECT 0.300 20.352 122.604 20.448 ;
      RECT 0.300 21.120 122.604 21.216 ;
      RECT 0.300 21.888 122.604 21.984 ;
      RECT 0.300 22.656 122.604 22.752 ;
      RECT 0.300 23.424 122.604 23.520 ;
      RECT 0.300 24.192 122.604 24.288 ;
      RECT 0.300 24.960 122.604 25.056 ;
      RECT 0.300 25.728 122.604 25.824 ;
      RECT 0.300 26.496 122.604 26.592 ;
      RECT 0.300 27.264 122.604 27.360 ;
      RECT 0.300 28.032 122.604 28.128 ;
      RECT 0.300 28.800 122.604 28.896 ;
      RECT 0.300 29.568 122.604 29.664 ;
      RECT 0.300 30.336 122.604 30.432 ;
      RECT 0.300 31.104 122.604 31.200 ;
      RECT 0.300 31.872 122.604 31.968 ;
      RECT 0.300 32.640 122.604 32.736 ;
      RECT 0.300 33.408 122.604 33.504 ;
      RECT 0.300 34.176 122.604 34.272 ;
      RECT 0.300 34.944 122.604 35.040 ;
      RECT 0.300 35.712 122.604 35.808 ;
      RECT 0.300 36.480 122.604 36.576 ;
      RECT 0.300 37.248 122.604 37.344 ;
      RECT 0.300 38.016 122.604 38.112 ;
      RECT 0.300 38.784 122.604 38.880 ;
      RECT 0.300 39.552 122.604 39.648 ;
      RECT 0.300 40.320 122.604 40.416 ;
      RECT 0.300 41.088 122.604 41.184 ;
      RECT 0.300 41.856 122.604 41.952 ;
      RECT 0.300 42.624 122.604 42.720 ;
      RECT 0.300 43.392 122.604 43.488 ;
      RECT 0.300 44.160 122.604 44.256 ;
      RECT 0.300 44.928 122.604 45.024 ;
      RECT 0.300 45.696 122.604 45.792 ;
      RECT 0.300 46.464 122.604 46.560 ;
      RECT 0.300 47.232 122.604 47.328 ;
      RECT 0.300 48.000 122.604 48.096 ;
      RECT 0.300 48.768 122.604 48.864 ;
      RECT 0.300 49.536 122.604 49.632 ;
      RECT 0.300 50.304 122.604 50.400 ;
      RECT 0.300 51.072 122.604 51.168 ;
      RECT 0.300 51.840 122.604 51.936 ;
      RECT 0.300 52.608 122.604 52.704 ;
      RECT 0.300 53.376 122.604 53.472 ;
      RECT 0.300 54.144 122.604 54.240 ;
      RECT 0.300 54.912 122.604 55.008 ;
      RECT 0.300 55.680 122.604 55.776 ;
      RECT 0.300 56.448 122.604 56.544 ;
      RECT 0.300 57.216 122.604 57.312 ;
      RECT 0.300 57.984 122.604 58.080 ;
      RECT 0.300 58.752 122.604 58.848 ;
      RECT 0.300 59.520 122.604 59.616 ;
      RECT 0.300 60.288 122.604 60.384 ;
      RECT 0.300 61.056 122.604 61.152 ;
      RECT 0.300 61.824 122.604 61.920 ;
      RECT 0.300 62.592 122.604 62.688 ;
      RECT 0.300 63.360 122.604 63.456 ;
      RECT 0.300 64.128 122.604 64.224 ;
      RECT 0.300 64.896 122.604 64.992 ;
      RECT 0.300 65.664 122.604 65.760 ;
    END
  END VDD
  PIN VSS
    DIRECTION INOUT ;
    USE GROUND ;
    PORT
      LAYER M4 ;
      RECT 0.300 0.768 122.604 0.864 ;
      RECT 0.300 1.536 122.604 1.632 ;
      RECT 0.300 2.304 122.604 2.400 ;
      RECT 0.300 3.072 122.604 3.168 ;
      RECT 0.300 3.840 122.604 3.936 ;
      RECT 0.300 4.608 122.604 4.704 ;
      RECT 0.300 5.376 122.604 5.472 ;
      RECT 0.300 6.144 122.604 6.240 ;
      RECT 0.300 6.912 122.604 7.008 ;
      RECT 0.300 7.680 122.604 7.776 ;
      RECT 0.300 8.448 122.604 8.544 ;
      RECT 0.300 9.216 122.604 9.312 ;
      RECT 0.300 9.984 122.604 10.080 ;
      RECT 0.300 10.752 122.604 10.848 ;
      RECT 0.300 11.520 122.604 11.616 ;
      RECT 0.300 12.288 122.604 12.384 ;
      RECT 0.300 13.056 122.604 13.152 ;
      RECT 0.300 13.824 122.604 13.920 ;
      RECT 0.300 14.592 122.604 14.688 ;
      RECT 0.300 15.360 122.604 15.456 ;
      RECT 0.300 16.128 122.604 16.224 ;
      RECT 0.300 16.896 122.604 16.992 ;
      RECT 0.300 17.664 122.604 17.760 ;
      RECT 0.300 18.432 122.604 18.528 ;
      RECT 0.300 19.200 122.604 19.296 ;
      RECT 0.300 19.968 122.604 20.064 ;
      RECT 0.300 20.736 122.604 20.832 ;
      RECT 0.300 21.504 122.604 21.600 ;
      RECT 0.300 22.272 122.604 22.368 ;
      RECT 0.300 23.040 122.604 23.136 ;
      RECT 0.300 23.808 122.604 23.904 ;
      RECT 0.300 24.576 122.604 24.672 ;
      RECT 0.300 25.344 122.604 25.440 ;
      RECT 0.300 26.112 122.604 26.208 ;
      RECT 0.300 26.880 122.604 26.976 ;
      RECT 0.300 27.648 122.604 27.744 ;
      RECT 0.300 28.416 122.604 28.512 ;
      RECT 0.300 29.184 122.604 29.280 ;
      RECT 0.300 29.952 122.604 30.048 ;
      RECT 0.300 30.720 122.604 30.816 ;
      RECT 0.300 31.488 122.604 31.584 ;
      RECT 0.300 32.256 122.604 32.352 ;
      RECT 0.300 33.024 122.604 33.120 ;
      RECT 0.300 33.792 122.604 33.888 ;
      RECT 0.300 34.560 122.604 34.656 ;
      RECT 0.300 35.328 122.604 35.424 ;
      RECT 0.300 36.096 122.604 36.192 ;
      RECT 0.300 36.864 122.604 36.960 ;
      RECT 0.300 37.632 122.604 37.728 ;
      RECT 0.300 38.400 122.604 38.496 ;
      RECT 0.300 39.168 122.604 39.264 ;
      RECT 0.300 39.936 122.604 40.032 ;
      RECT 0.300 40.704 122.604 40.800 ;
      RECT 0.300 41.472 122.604 41.568 ;
      RECT 0.300 42.240 122.604 42.336 ;
      RECT 0.300 43.008 122.604 43.104 ;
      RECT 0.300 43.776 122.604 43.872 ;
      RECT 0.300 44.544 122.604 44.640 ;
      RECT 0.300 45.312 122.604 45.408 ;
      RECT 0.300 46.080 122.604 46.176 ;
      RECT 0.300 46.848 122.604 46.944 ;
      RECT 0.300 47.616 122.604 47.712 ;
      RECT 0.300 48.384 122.604 48.480 ;
      RECT 0.300 49.152 122.604 49.248 ;
      RECT 0.300 49.920 122.604 50.016 ;
      RECT 0.300 50.688 122.604 50.784 ;
      RECT 0.300 51.456 122.604 51.552 ;
      RECT 0.300 52.224 122.604 52.320 ;
      RECT 0.300 52.992 122.604 53.088 ;
      RECT 0.300 53.760 122.604 53.856 ;
      RECT 0.300 54.528 122.604 54.624 ;
      RECT 0.300 55.296 122.604 55.392 ;
      RECT 0.300 56.064 122.604 56.160 ;
      RECT 0.300 56.832 122.604 56.928 ;
      RECT 0.300 57.600 122.604 57.696 ;
      RECT 0.300 58.368 122.604 58.464 ;
      RECT 0.300 59.136 122.604 59.232 ;
      RECT 0.300 59.904 122.604 60.000 ;
      RECT 0.300 60.672 122.604 60.768 ;
      RECT 0.300 61.440 122.604 61.536 ;
      RECT 0.300 62.208 122.604 62.304 ;
      RECT 0.300 62.976 122.604 63.072 ;
      RECT 0.300 63.744 122.604 63.840 ;
      RECT 0.300 64.512 122.604 64.608 ;
      RECT 0.300 65.280 122.604 65.376 ;
      RECT 0.300 66.048 122.604 66.144 ;
    END
  END VSS
  OBS
    LAYER M1 ;
    RECT 0 0 122.904 66.150 ;
    LAYER M2 ;
    RECT 0 0 122.904 66.150 ;
    LAYER M3 ;
    RECT 0 0 122.904 66.150 ;
    LAYER M4 ;
    RECT 0.072 0 122.832 66.150 ;
  END
END ot_sram_1rw_2048x128_m4_r2c2

END LIBRARY
